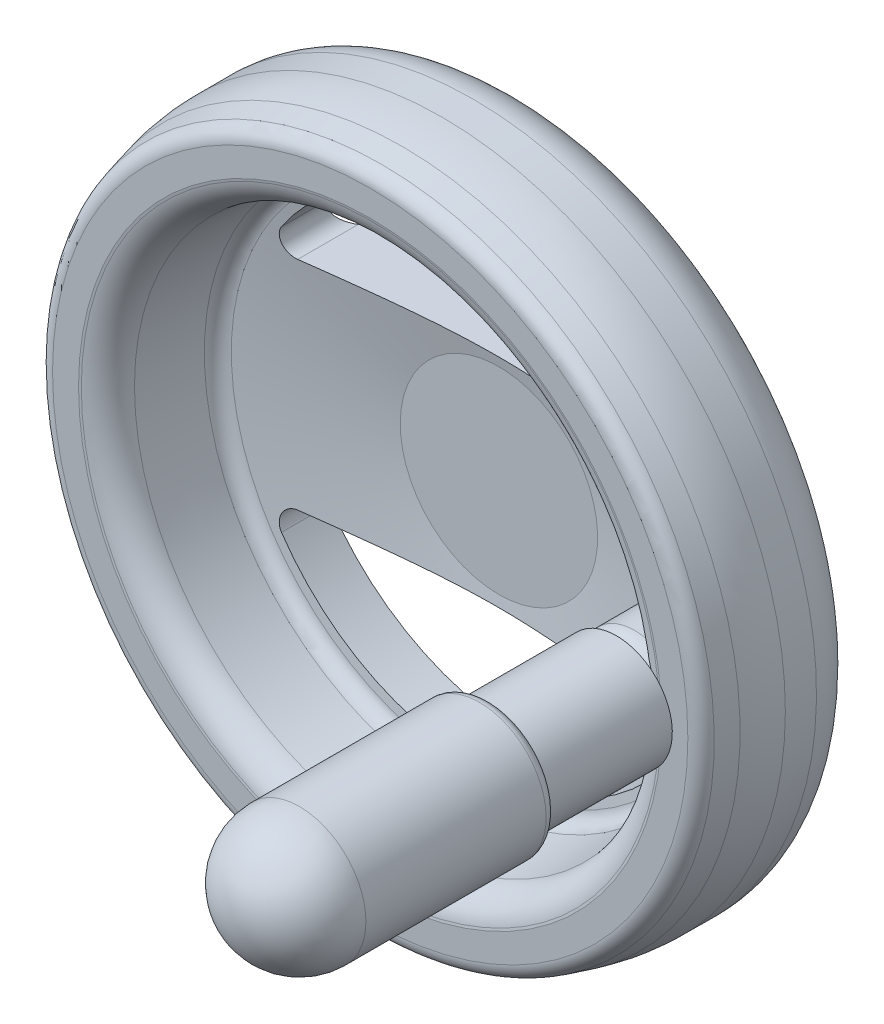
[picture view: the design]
ISO-10303-21;
HEADER;
FILE_DESCRIPTION(('STEP AP214'),'2;1');
FILE_NAME('part.step','',(''),(''),'','','');
FILE_SCHEMA(('AUTOMOTIVE_DESIGN { 1 0 10303 214 1 1 1 1 }'));
ENDSEC;
DATA;
#1=APPLICATION_CONTEXT('core data for automotive mechanical design processes');
#2=APPLICATION_PROTOCOL_DEFINITION('international standard','automotive_design',2000,#1);
#3=PRODUCT_CONTEXT('',#1,'mechanical');
#4=PRODUCT('Part','Part','',(#3));
#5=PRODUCT_RELATED_PRODUCT_CATEGORY('part','',(#4));
#6=PRODUCT_DEFINITION_FORMATION('','',#4);
#7=PRODUCT_DEFINITION_CONTEXT('part definition',#1,'design');
#8=PRODUCT_DEFINITION('design','',#6,#7);
#9=PRODUCT_DEFINITION_SHAPE('','',#8);
#10=(LENGTH_UNIT() NAMED_UNIT(*) SI_UNIT(.MILLI.,.METRE.));
#11=(NAMED_UNIT(*) PLANE_ANGLE_UNIT() SI_UNIT($,.RADIAN.));
#12=(NAMED_UNIT(*) SI_UNIT($,.STERADIAN.) SOLID_ANGLE_UNIT());
#13=UNCERTAINTY_MEASURE_WITH_UNIT(LENGTH_MEASURE(1.E-05),#10,'distance_accuracy_value','');
#14=(GEOMETRIC_REPRESENTATION_CONTEXT(3) GLOBAL_UNCERTAINTY_ASSIGNED_CONTEXT((#13)) GLOBAL_UNIT_ASSIGNED_CONTEXT((#10,
#11,#12)) REPRESENTATION_CONTEXT('',''));
#15=CARTESIAN_POINT('',(0.,0.,0.));
#16=DIRECTION('',(0.,0.,1.));
#17=DIRECTION('',(1.,0.,0.));
#18=AXIS2_PLACEMENT_3D('',#15,#16,#17);
#19=CARTESIAN_POINT('',(29.,0.,33.2));
#20=DIRECTION('',(0.,0.,-1.));
#21=DIRECTION('',(0.,1.,0.));
#22=AXIS2_PLACEMENT_3D('',#19,#20,#21);
#23=TOROIDAL_SURFACE('',#22,4.2,1.8);
#24=CARTESIAN_POINT('',(30.6761601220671,5.76111857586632,33.2));
#25=CARTESIAN_POINT('',(30.7059480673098,5.75244726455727,33.2481599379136));
#26=CARTESIAN_POINT('',(30.7369578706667,5.74116772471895,33.294989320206));
#27=CARTESIAN_POINT('',(30.8008570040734,5.71399772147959,33.3857792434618));
#28=CARTESIAN_POINT('',(30.8337414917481,5.69811874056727,33.429746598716));
#29=CARTESIAN_POINT('',(30.933707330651,5.64487432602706,33.5562676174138));
#30=CARTESIAN_POINT('',(31.0029129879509,5.60164089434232,33.6347145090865));
#31=CARTESIAN_POINT('',(31.1222333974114,5.51828977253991,33.7583522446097));
#32=CARTESIAN_POINT('',(31.1717108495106,5.48126584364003,33.8063746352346));
#33=CARTESIAN_POINT('',(31.2712263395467,5.40234334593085,33.8976094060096));
#34=CARTESIAN_POINT('',(31.3212644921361,5.36044376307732,33.9408207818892));
#35=CARTESIAN_POINT('',(31.4719915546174,5.22801287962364,34.0643305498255));
#36=CARTESIAN_POINT('',(31.5726915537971,5.13117834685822,34.1379051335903));
#37=CARTESIAN_POINT('',(31.7517457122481,4.94506324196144,34.2574365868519));
#38=CARTESIAN_POINT('',(31.8306722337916,4.85791259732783,34.3059835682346));
#39=CARTESIAN_POINT('',(31.9855051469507,4.67691643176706,34.3948959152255));
#40=CARTESIAN_POINT('',(32.0614097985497,4.58306713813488,34.4352566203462));
#41=CARTESIAN_POINT('',(32.2093597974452,4.38982890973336,34.5089751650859));
#42=CARTESIAN_POINT('',(32.2814060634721,4.29044130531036,34.5423346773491));
#43=CARTESIAN_POINT('',(32.4211196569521,4.08687545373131,34.6031213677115));
#44=CARTESIAN_POINT('',(32.4887858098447,3.9826959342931,34.6305469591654));
#45=CARTESIAN_POINT('',(32.6493058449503,3.72128500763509,34.6918239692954));
#46=CARTESIAN_POINT('',(32.7394256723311,3.56169671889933,34.7228268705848));
#47=CARTESIAN_POINT('',(32.9082571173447,3.23521266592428,34.7764231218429));
#48=CARTESIAN_POINT('',(32.9869639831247,3.06831389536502,34.7990129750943));
#49=CARTESIAN_POINT('',(33.1321341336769,2.72842101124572,34.8376545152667));
#50=CARTESIAN_POINT('',(33.1985893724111,2.5554229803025,34.853701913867));
#51=CARTESIAN_POINT('',(33.3184989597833,2.20463008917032,34.8807503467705));
#52=CARTESIAN_POINT('',(33.3719549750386,2.02683584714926,34.8917520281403));
#53=CARTESIAN_POINT('',(33.4662247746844,1.66421200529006,34.9100738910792));
#54=CARTESIAN_POINT('',(33.5067858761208,1.47931308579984,34.9173220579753));
#55=CARTESIAN_POINT('',(33.5735207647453,1.10684047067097,34.9287586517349));
#56=CARTESIAN_POINT('',(33.5996940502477,0.919266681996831,34.9329469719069));
#57=CARTESIAN_POINT('',(33.6374405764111,0.542670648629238,34.9388668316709));
#58=CARTESIAN_POINT('',(33.6490178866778,0.35364882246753,34.9405990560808));
#59=CARTESIAN_POINT('',(33.6575111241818,-0.0247321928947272,34.9418765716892));
#60=CARTESIAN_POINT('',(33.6544266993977,-0.214091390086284,34.9414218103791));
#61=CARTESIAN_POINT('',(33.6328597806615,-0.605655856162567,34.9381417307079));
#62=CARTESIAN_POINT('',(33.6132803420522,-0.807800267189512,34.9351474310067));
#63=CARTESIAN_POINT('',(33.5574365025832,-1.2097216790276,34.9260465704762));
#64=CARTESIAN_POINT('',(33.5211703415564,-1.40949842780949,34.9199396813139));
#65=CARTESIAN_POINT('',(33.4322821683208,-1.8053600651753,34.9036466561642));
#66=CARTESIAN_POINT('',(33.3796486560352,-2.00144225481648,34.893457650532));
#67=CARTESIAN_POINT('',(33.2586335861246,-2.3882898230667,34.8676070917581));
#68=CARTESIAN_POINT('',(33.190255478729,-2.57905635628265,34.8519467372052));
#69=CARTESIAN_POINT('',(33.0531328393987,-2.91785381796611,34.8170102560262));
#70=CARTESIAN_POINT('',(32.9869716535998,-3.06706637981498,34.7990028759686));
#71=CARTESIAN_POINT('',(32.8454480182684,-3.36022800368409,34.7569856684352));
#72=CARTESIAN_POINT('',(32.7700847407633,-3.50417659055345,34.7329753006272));
#73=CARTESIAN_POINT('',(32.6110214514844,-3.78548180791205,34.6775610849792));
#74=CARTESIAN_POINT('',(32.5273417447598,-3.9228533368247,34.6461750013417));
#75=CARTESIAN_POINT('',(32.3524095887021,-4.19007675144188,34.5742526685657));
#76=CARTESIAN_POINT('',(32.2611615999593,-4.31993299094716,34.5337217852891));
#77=CARTESIAN_POINT('',(32.0609092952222,-4.58555207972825,34.4358787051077));
#78=CARTESIAN_POINT('',(31.9510808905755,-4.72019973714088,34.377149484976));
#79=CARTESIAN_POINT('',(31.7819752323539,-4.91125842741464,34.2756717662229));
#80=CARTESIAN_POINT('',(31.7248471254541,-4.97315666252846,34.2395918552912));
#81=CARTESIAN_POINT('',(31.6095673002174,-5.09270339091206,34.1624008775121));
#82=CARTESIAN_POINT('',(31.5514158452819,-5.1503529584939,34.1212910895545));
#83=CARTESIAN_POINT('',(31.4063616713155,-5.28735403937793,34.0121924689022));
#84=CARTESIAN_POINT('',(31.3191359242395,-5.36374138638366,33.9408104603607));
#85=CARTESIAN_POINT('',(31.1464858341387,-5.50180113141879,33.7838796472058));
#86=CARTESIAN_POINT('',(31.0610543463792,-5.56355012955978,33.6984087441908));
#87=CARTESIAN_POINT('',(30.924797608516,-5.64924722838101,33.5444135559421));
#88=CARTESIAN_POINT('',(30.8723720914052,-5.67885122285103,33.4805071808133));
#89=CARTESIAN_POINT('',(30.7710499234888,-5.72811723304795,33.345539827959));
#90=CARTESIAN_POINT('',(30.7221859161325,-5.74769530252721,33.2744242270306));
#91=CARTESIAN_POINT('',(30.6761601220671,-5.76111857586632,33.2));
#92=B_SPLINE_CURVE_WITH_KNOTS('',3,(#24,#25,#26,#27,#28,#29,#30,#31,#32,#33,#34,#35,#36,#37,#38,
#39,#40,#41,#42,#43,#44,#45,#46,#47,#48,#49,#50,#51,#52,#53,#54,#55,#56,#57,#58,#59,#60,#61,#62,
#63,#64,#65,#66,#67,#68,#69,#70,#71,#72,#73,#74,#75,#76,#77,#78,#79,#80,#81,#82,#83,#84,#85,#86,
#87,#88,#89,#90,#91),.UNSPECIFIED.,.F.,.F.,(4,2,2,2,2,2,2,2,2,2,2,2,2,2,2,2,2,2,2,2,2,2,2,2,2,2,
2,2,2,2,2,2,2,4),(0.,0.17163547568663,0.342846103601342,0.68073967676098,0.915252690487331,
1.1498145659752,1.62175863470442,2.00292112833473,2.38430001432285,2.76558768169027,
3.1469771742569,3.70382900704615,4.2609120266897,4.81835960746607,5.37573568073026,
5.94344251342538,6.51116914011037,7.07873743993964,7.64631936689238,8.25492939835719,
8.86360364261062,9.47270652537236,10.0816760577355,10.573899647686,11.0661675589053,
11.557261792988,12.0480686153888,12.5968709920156,12.8715722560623,13.1462038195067,
13.5534597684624,13.9585350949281,14.2210901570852,14.4858090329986),.UNSPECIFIED.);
#93=CARTESIAN_POINT('',(30.6761601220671,5.76111857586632,33.2));
#94=VERTEX_POINT('',#93);
#95=CARTESIAN_POINT('',(30.6761601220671,-5.76111857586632,33.2));
#96=VERTEX_POINT('',#95);
#97=EDGE_CURVE('E163',#94,#96,#92,.T.);
#98=ORIENTED_EDGE('',*,*,#97,.F.);
#99=CARTESIAN_POINT('',(29.,0.,33.2));
#100=DIRECTION('',(0.,0.,1.));
#101=DIRECTION('',(0.,-1.,0.));
#102=AXIS2_PLACEMENT_3D('',#99,#100,#101);
#103=CIRCLE('',#102,6.);
#104=EDGE_CURVE('E159',#96,#94,#103,.F.);
#105=ORIENTED_EDGE('',*,*,#104,.F.);
#106=EDGE_LOOP('',(#98,#105));
#107=FACE_BOUND('',#106,.T.);
#108=CARTESIAN_POINT('',(29.,0.,35.));
#109=DIRECTION('',(0.,0.,-1.));
#110=DIRECTION('',(0.,-1.,0.));
#111=AXIS2_PLACEMENT_3D('',#108,#109,#110);
#112=CIRCLE('',#111,4.2);
#113=CARTESIAN_POINT('',(29.,-4.2,35.));
#114=VERTEX_POINT('',#113);
#115=CARTESIAN_POINT('',(24.8,0.,35.));
#116=VERTEX_POINT('',#115);
#117=EDGE_CURVE('E31',#114,#116,#112,.T.);
#118=ORIENTED_EDGE('',*,*,#117,.T.);
#119=CARTESIAN_POINT('',(29.,0.,35.));
#120=DIRECTION('',(0.,0.,-1.));
#121=DIRECTION('',(-1.,0.,0.));
#122=AXIS2_PLACEMENT_3D('',#119,#120,#121);
#123=CIRCLE('',#122,4.19999999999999);
#124=CARTESIAN_POINT('',(29.,4.2,35.));
#125=VERTEX_POINT('',#124);
#126=EDGE_CURVE('E788',#116,#125,#123,.T.);
#127=ORIENTED_EDGE('',*,*,#126,.T.);
#128=CARTESIAN_POINT('',(29.,0.,35.));
#129=DIRECTION('',(0.,0.,-1.));
#130=DIRECTION('',(0.,1.,0.));
#131=AXIS2_PLACEMENT_3D('',#128,#129,#130);
#132=CIRCLE('',#131,4.2);
#133=EDGE_CURVE('E786',#125,#114,#132,.T.);
#134=ORIENTED_EDGE('',*,*,#133,.T.);
#135=EDGE_LOOP('',(#118,#127,#134));
#136=FACE_BOUND('',#135,.T.);
#137=ADVANCED_FACE('F14',(#107,#136),#23,.T.);
#138=CARTESIAN_POINT('',(0.,0.,31.4060347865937));
#139=DIRECTION('',(0.,0.,-1.));
#140=DIRECTION('',(0.,1.,0.));
#141=AXIS2_PLACEMENT_3D('',#138,#139,#140);
#142=TOROIDAL_SURFACE('',#141,34.3336218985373,3.6);
#143=CARTESIAN_POINT('',(30.6761601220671,-5.76111857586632,33.2));
#144=CARTESIAN_POINT('',(30.6273849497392,-5.77530049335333,33.1211928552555));
#145=CARTESIAN_POINT('',(30.5816886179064,-5.78793211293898,33.0402070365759));
#146=CARTESIAN_POINT('',(30.4968646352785,-5.81045182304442,32.874468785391));
#147=CARTESIAN_POINT('',(30.4577389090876,-5.82033911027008,32.7897152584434));
#148=CARTESIAN_POINT('',(30.3871954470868,-5.83754874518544,32.6187736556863));
#149=CARTESIAN_POINT('',(30.3556414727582,-5.84491763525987,32.5326464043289));
#150=CARTESIAN_POINT('',(30.2995651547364,-5.8576409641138,32.3580312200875));
#151=CARTESIAN_POINT('',(30.2750393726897,-5.8629963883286,32.2695444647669));
#152=CARTESIAN_POINT('',(30.2364864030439,-5.87123762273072,32.1047832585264));
#153=CARTESIAN_POINT('',(30.2214171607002,-5.87437868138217,32.0287632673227));
#154=CARTESIAN_POINT('',(30.1963946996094,-5.87952217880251,31.8751872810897));
#155=CARTESIAN_POINT('',(30.1864857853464,-5.88151477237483,31.7976237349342));
#156=CARTESIAN_POINT('',(30.1792715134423,-5.88296852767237,31.7197954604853));
#157=B_SPLINE_CURVE_WITH_KNOTS('',3,(#143,#144,#145,#146,#147,#148,#149,#150,#151,#152,#153,
#154,#155,#156),.UNSPECIFIED.,.F.,.F.,(4,2,2,2,2,2,4),(0.,0.281182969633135,0.562448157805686,
0.838191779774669,1.11380027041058,1.3463037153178,1.58077173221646),.UNSPECIFIED.);
#158=CARTESIAN_POINT('',(30.1792715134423,-5.88296852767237,31.7197954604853));
#159=VERTEX_POINT('',#158);
#160=EDGE_CURVE('E170',#96,#159,#157,.T.);
#161=ORIENTED_EDGE('',*,*,#160,.T.);
#162=CARTESIAN_POINT('',(0.,0.,31.7197954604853));
#163=DIRECTION('',(0.,0.,1.));
#164=DIRECTION('',(-1.,0.,0.));
#165=AXIS2_PLACEMENT_3D('',#162,#163,#164);
#166=CIRCLE('',#165,30.747320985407);
#167=CARTESIAN_POINT('',(30.1792715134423,5.88296852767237,31.7197954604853));
#168=VERTEX_POINT('',#167);
#169=EDGE_CURVE('E167',#159,#168,#166,.F.);
#170=ORIENTED_EDGE('',*,*,#169,.T.);
#171=CARTESIAN_POINT('',(30.1792715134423,5.88296852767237,31.7197954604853));
#172=CARTESIAN_POINT('',(30.1879164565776,5.88121949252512,31.8131314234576));
#173=CARTESIAN_POINT('',(30.2004481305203,5.87870326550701,31.9060945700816));
#174=CARTESIAN_POINT('',(30.2331330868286,5.8719427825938,32.0906530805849));
#175=CARTESIAN_POINT('',(30.2532899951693,5.86769770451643,32.1822477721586));
#176=CARTESIAN_POINT('',(30.3005923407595,5.85739017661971,32.3615651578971));
#177=CARTESIAN_POINT('',(30.3275915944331,5.85136535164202,32.4493286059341));
#178=CARTESIAN_POINT('',(30.3885029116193,5.83721157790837,32.6221992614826));
#179=CARTESIAN_POINT('',(30.4224111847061,5.82908378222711,32.7073078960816));
#180=CARTESIAN_POINT('',(30.4910071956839,5.81187963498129,32.8612425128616));
#181=CARTESIAN_POINT('',(30.5247435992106,5.80315045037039,32.9305332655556));
#182=CARTESIAN_POINT('',(30.5969698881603,5.783691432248,33.0670662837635));
#183=CARTESIAN_POINT('',(30.6354977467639,5.77294522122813,33.1342861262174));
#184=CARTESIAN_POINT('',(30.6761601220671,5.76111857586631,33.2));
#185=B_SPLINE_CURVE_WITH_KNOTS('',3,(#171,#172,#173,#174,#175,#176,#177,#178,#179,#180,#181,
#182,#183,#184),.UNSPECIFIED.,.F.,.F.,(4,2,2,2,2,2,4),(0.,0.281175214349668,0.562484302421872,
0.838226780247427,1.11381838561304,1.34630753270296,1.58077317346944),.UNSPECIFIED.);
#186=EDGE_CURVE('E152',#168,#94,#185,.T.);
#187=ORIENTED_EDGE('',*,*,#186,.T.);
#188=ORIENTED_EDGE('',*,*,#97,.T.);
#189=EDGE_LOOP('',(#161,#170,#187,#188));
#190=FACE_BOUND('',#189,.T.);
#191=CARTESIAN_POINT('',(0.,0.,34.9513426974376));
#192=DIRECTION('',(0.,0.,1.));
#193=DIRECTION('',(-1.,0.,0.));
#194=AXIS2_PLACEMENT_3D('',#191,#192,#193);
#195=CIRCLE('',#194,33.7084884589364);
#196=CARTESIAN_POINT('',(-33.7084884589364,0.,34.9513426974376));
#197=VERTEX_POINT('',#196);
#198=EDGE_CURVE('E174',#197,#197,#195,.T.);
#199=ORIENTED_EDGE('',*,*,#198,.T.);
#200=EDGE_LOOP('',(#199));
#201=FACE_BOUND('',#200,.T.);
#202=ADVANCED_FACE('F168',(#190,#201),#142,.T.);
#203=CARTESIAN_POINT('',(29.,0.,26.6));
#204=DIRECTION('',(0.,0.,1.));
#205=DIRECTION('',(0.,-1.,0.));
#206=AXIS2_PLACEMENT_3D('',#203,#204,#205);
#207=CYLINDRICAL_SURFACE('',#206,6.);
#208=ORIENTED_EDGE('',*,*,#160,.F.);
#209=ORIENTED_EDGE('',*,*,#104,.T.);
#210=ORIENTED_EDGE('',*,*,#186,.F.);
#211=CARTESIAN_POINT('',(30.1792715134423,5.88296852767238,31.7197954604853));
#212=CARTESIAN_POINT('',(30.1214154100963,5.89456507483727,31.0960777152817));
#213=CARTESIAN_POINT('',(30.0637104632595,5.90524557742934,30.4723290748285));
#214=CARTESIAN_POINT('',(29.9486039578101,5.92482587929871,29.2247807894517));
#215=CARTESIAN_POINT('',(29.8912023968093,5.93372569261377,28.6009811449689));
#216=CARTESIAN_POINT('',(29.7767028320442,5.94979618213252,27.3533318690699));
#217=CARTESIAN_POINT('',(29.7196048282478,5.9569668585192,26.729482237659));
#218=CARTESIAN_POINT('',(29.605712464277,5.96962251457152,25.4817331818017));
#219=CARTESIAN_POINT('',(29.5489181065,5.97510748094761,24.8578337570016));
#220=CARTESIAN_POINT('',(29.4922760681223,5.97977125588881,24.2339144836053));
#221=B_SPLINE_CURVE_WITH_KNOTS('',3,(#211,#212,#213,#214,#215,#216,#217,#218,#219,#220),
.UNSPECIFIED.,.F.,.F.,(4,2,2,2,4),(0.,1.87950718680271,3.75899955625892,5.63849172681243,
7.51799871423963),.UNSPECIFIED.);
#222=CARTESIAN_POINT('',(29.4922760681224,5.9797712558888,24.2339144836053));
#223=VERTEX_POINT('',#222);
#224=EDGE_CURVE('E158',#168,#223,#221,.T.);
#225=ORIENTED_EDGE('',*,*,#224,.T.);
#226=CARTESIAN_POINT('',(29.4922760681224,5.9797712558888,24.2339144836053));
#227=CARTESIAN_POINT('',(29.4877633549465,5.98013823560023,24.1841300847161));
#228=CARTESIAN_POINT('',(29.4810885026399,5.98068702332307,24.1345484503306));
#229=CARTESIAN_POINT('',(29.4635155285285,5.98207700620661,24.0361553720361));
#230=CARTESIAN_POINT('',(29.4526184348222,5.9829181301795,23.9873437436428));
#231=CARTESIAN_POINT('',(29.4267261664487,5.98481988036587,23.890929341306));
#232=CARTESIAN_POINT('',(29.411739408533,5.98588005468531,23.8433243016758));
#233=CARTESIAN_POINT('',(29.37781218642,5.98811711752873,23.7495603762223));
#234=CARTESIAN_POINT('',(29.3588715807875,5.9892940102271,23.7034015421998));
#235=CARTESIAN_POINT('',(29.2963784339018,5.99282142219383,23.5676081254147));
#236=CARTESIAN_POINT('',(29.24711826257,5.99517190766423,23.4805228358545));
#237=CARTESIAN_POINT('',(29.1350562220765,5.99874082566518,23.3155665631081));
#238=CARTESIAN_POINT('',(29.0722493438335,5.99995883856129,23.2376990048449));
#239=CARTESIAN_POINT('',(28.9332068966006,6.0000400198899,23.0912280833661));
#240=CARTESIAN_POINT('',(28.8566741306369,5.99884338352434,23.0229059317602));
#241=CARTESIAN_POINT('',(28.6935876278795,5.9927259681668,22.8997674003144));
#242=CARTESIAN_POINT('',(28.6070362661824,5.98780607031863,22.8449478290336));
#243=CARTESIAN_POINT('',(28.4283761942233,5.97336344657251,22.7514437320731));
#244=CARTESIAN_POINT('',(28.3364353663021,5.9639462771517,22.7124253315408));
#245=CARTESIAN_POINT('',(28.195137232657,5.94596268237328,22.6656263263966));
#246=CARTESIAN_POINT('',(28.1474093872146,5.93931406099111,22.6519713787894));
#247=CARTESIAN_POINT('',(28.0511658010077,5.92470164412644,22.6286882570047));
#248=CARTESIAN_POINT('',(28.0026498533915,5.91673749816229,22.6190611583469));
#249=CARTESIAN_POINT('',(27.9539057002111,5.90810347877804,22.6114933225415));
#250=B_SPLINE_CURVE_WITH_KNOTS('',3,(#226,#227,#228,#229,#230,#231,#232,#233,#234,#235,#236,
#237,#238,#239,#240,#241,#242,#243,#244,#245,#246,#247,#248,#249),.UNSPECIFIED.,.F.,.F.,(4,2,2,
2,2,2,2,2,2,2,2,4),(0.,0.149914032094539,0.299791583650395,0.449362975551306,0.598939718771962,
0.897682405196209,1.19653574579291,1.50288175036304,1.80915527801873,2.10856926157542,
2.25866534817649,2.40880148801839),.UNSPECIFIED.);
#251=CARTESIAN_POINT('',(27.9539057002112,5.90810347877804,22.6114933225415));
#252=VERTEX_POINT('',#251);
#253=EDGE_CURVE('E180',#223,#252,#250,.T.);
#254=ORIENTED_EDGE('',*,*,#253,.T.);
#255=CARTESIAN_POINT('',(27.9539057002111,5.90810347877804,22.6114933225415));
#256=CARTESIAN_POINT('',(27.7862920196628,5.87844291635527,22.5854705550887));
#257=CARTESIAN_POINT('',(27.6199550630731,5.84161839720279,22.5594087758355));
#258=CARTESIAN_POINT('',(27.2909958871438,5.75397455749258,22.5074010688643));
#259=CARTESIAN_POINT('',(27.1283735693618,5.70315560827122,22.4814551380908));
#260=CARTESIAN_POINT('',(26.8080422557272,5.58787107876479,22.4298790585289));
#261=CARTESIAN_POINT('',(26.6503318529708,5.52340944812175,22.4042488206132));
#262=CARTESIAN_POINT('',(26.3408962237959,5.38127779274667,22.3535020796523));
#263=CARTESIAN_POINT('',(26.1891709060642,5.30360796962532,22.3283855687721));
#264=CARTESIAN_POINT('',(25.8927248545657,5.13555110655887,22.2788688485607));
#265=CARTESIAN_POINT('',(25.7480070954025,5.04515872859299,22.2544689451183));
#266=CARTESIAN_POINT('',(25.4666352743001,4.85226122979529,22.2066091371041));
#267=CARTESIAN_POINT('',(25.3299842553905,4.7497515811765,22.1831495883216));
#268=CARTESIAN_POINT('',(25.0659039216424,4.53343124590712,22.1374257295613));
#269=CARTESIAN_POINT('',(24.9384675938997,4.41962931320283,22.1151605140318));
#270=CARTESIAN_POINT('',(24.6935864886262,4.1813869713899,22.072027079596));
#271=CARTESIAN_POINT('',(24.5761462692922,4.05694176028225,22.0511594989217));
#272=CARTESIAN_POINT('',(24.3528772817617,3.79909969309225,22.0111845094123));
#273=CARTESIAN_POINT('',(24.2469830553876,3.66576104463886,21.9920672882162));
#274=CARTESIAN_POINT('',(24.0468497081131,3.39046440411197,21.955685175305));
#275=CARTESIAN_POINT('',(23.9526051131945,3.24851050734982,21.9384194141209));
#276=CARTESIAN_POINT('',(23.7763614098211,2.95679942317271,21.9059303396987));
#277=CARTESIAN_POINT('',(23.6943729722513,2.80703558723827,21.8907088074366));
#278=CARTESIAN_POINT('',(23.5434120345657,2.5009516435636,21.8625316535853));
#279=CARTESIAN_POINT('',(23.4744348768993,2.34463390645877,21.8495752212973));
#280=CARTESIAN_POINT('',(23.344419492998,2.01222464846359,21.825046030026));
#281=CARTESIAN_POINT('',(23.2846504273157,1.83561799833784,21.8137020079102));
#282=CARTESIAN_POINT('',(23.1817610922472,1.47743750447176,21.7941056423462));
#283=CARTESIAN_POINT('',(23.1386424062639,1.2958631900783,21.7858535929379));
#284=CARTESIAN_POINT('',(23.0694882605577,0.929404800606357,21.7725905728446));
#285=CARTESIAN_POINT('',(23.0434499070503,0.744521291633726,21.7675790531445));
#286=CARTESIAN_POINT('',(23.0087071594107,0.373087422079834,21.760887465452));
#287=CARTESIAN_POINT('',(23.0000007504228,0.186537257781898,21.7592070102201));
#288=CARTESIAN_POINT('',(22.9999993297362,-0.166611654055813,21.7592066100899));
#289=CARTESIAN_POINT('',(23.0069438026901,-0.333213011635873,21.7605468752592));
#290=CARTESIAN_POINT('',(23.0346693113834,-0.665277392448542,21.7658885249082));
#291=CARTESIAN_POINT('',(23.055454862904,-0.830740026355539,21.7698907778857));
#292=CARTESIAN_POINT('',(23.1106845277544,-1.15917029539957,21.780495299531));
#293=CARTESIAN_POINT('',(23.1451196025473,-1.32213950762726,21.7870958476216));
#294=CARTESIAN_POINT('',(23.2273930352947,-1.64459904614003,21.8028051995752));
#295=CARTESIAN_POINT('',(23.2752363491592,-1.80408806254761,21.811914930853));
#296=CARTESIAN_POINT('',(23.3839138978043,-2.11829984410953,21.8325079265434));
#297=CARTESIAN_POINT('',(23.4447395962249,-2.27302566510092,21.8439896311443));
#298=CARTESIAN_POINT('',(23.5789596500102,-2.57680131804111,21.8691808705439));
#299=CARTESIAN_POINT('',(23.6523583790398,-2.72584915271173,21.8828911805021));
#300=CARTESIAN_POINT('',(23.8111449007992,-3.01716720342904,21.9123587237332));
#301=CARTESIAN_POINT('',(23.8965305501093,-3.15943862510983,21.9281155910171));
#302=CARTESIAN_POINT('',(24.0786731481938,-3.43627658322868,21.961487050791));
#303=CARTESIAN_POINT('',(24.1754302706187,-3.57084300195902,21.97910167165));
#304=CARTESIAN_POINT('',(24.3805453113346,-3.83256196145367,22.0161544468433));
#305=CARTESIAN_POINT('',(24.4890007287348,-3.9596359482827,22.0356077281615));
#306=CARTESIAN_POINT('',(24.7159568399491,-4.204139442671,22.0759799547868));
#307=CARTESIAN_POINT('',(24.8344542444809,-4.32157208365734,22.0968984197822));
#308=CARTESIAN_POINT('',(25.0807887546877,-4.54616180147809,22.1400098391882));
#309=CARTESIAN_POINT('',(25.2086337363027,-4.65331003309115,22.1622038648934));
#310=CARTESIAN_POINT('',(25.472631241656,-4.85648058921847,22.2076278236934));
#311=CARTESIAN_POINT('',(25.6087808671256,-4.95250676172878,22.2308573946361));
#312=CARTESIAN_POINT('',(25.8908207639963,-5.1343574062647,22.278544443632));
#313=CARTESIAN_POINT('',(26.0368356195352,-5.2199850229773,22.3030159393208));
#314=CARTESIAN_POINT('',(26.3354346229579,-5.37853646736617,22.3525972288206));
#315=CARTESIAN_POINT('',(26.4880163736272,-5.45146488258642,22.3777067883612));
#316=CARTESIAN_POINT('',(26.7984817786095,-5.58406412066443,22.4283267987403));
#317=CARTESIAN_POINT('',(26.9563569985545,-5.64375497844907,22.4538365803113));
#318=CARTESIAN_POINT('',(27.2764707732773,-5.7495945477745,22.5050884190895));
#319=CARTESIAN_POINT('',(27.4387067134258,-5.79575118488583,22.5308303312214));
#320=CARTESIAN_POINT('',(27.6607579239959,-5.84893313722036,22.5657467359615));
#321=CARTESIAN_POINT('',(27.7191764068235,-5.86200273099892,22.5749035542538));
#322=CARTESIAN_POINT('',(27.8363111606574,-5.88637413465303,22.5932058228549));
#323=CARTESIAN_POINT('',(27.8950270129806,-5.89767795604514,22.6023512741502));
#324=CARTESIAN_POINT('',(27.9539057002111,-5.90810347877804,22.6114933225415));
#325=B_SPLINE_CURVE_WITH_KNOTS('',3,(#255,#256,#257,#258,#259,#260,#261,#262,#263,#264,#265,
#266,#267,#268,#269,#270,#271,#272,#273,#274,#275,#276,#277,#278,#279,#280,#281,#282,#283,#284,
#285,#286,#287,#288,#289,#290,#291,#292,#293,#294,#295,#296,#297,#298,#299,#300,#301,#302,#303,
#304,#305,#306,#307,#308,#309,#310,#311,#312,#313,#314,#315,#316,#317,#318,#319,#320,#321,#322,
#323,#324),.UNSPECIFIED.,.F.,.F.,(4,2,2,2,2,2,2,2,2,2,2,2,2,2,2,2,2,2,2,2,2,2,2,2,2,2,2,2,2,2,2,
2,2,2,4),(0.,0.516430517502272,1.03284733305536,1.54911484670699,2.06537448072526,
2.58185137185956,3.09852186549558,3.61479491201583,4.13130213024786,4.64470942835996,
5.15787455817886,5.67148390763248,6.18490905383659,6.74444002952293,7.30402420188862,
7.86351354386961,8.42293784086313,8.92260535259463,9.42243596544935,9.92193614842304,
10.4216211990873,10.9209786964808,11.4205102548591,11.9199526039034,12.4194025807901,
12.9233947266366,13.427222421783,13.9314796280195,14.4355618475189,14.9480511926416,
15.4603550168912,15.9718781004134,16.483101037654,16.6647579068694,16.8462063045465),.UNSPECIFIED.);
#326=CARTESIAN_POINT('',(27.9539057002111,-5.90810347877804,22.6114933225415));
#327=VERTEX_POINT('',#326);
#328=EDGE_CURVE('E247',#252,#327,#325,.T.);
#329=ORIENTED_EDGE('',*,*,#328,.T.);
#330=CARTESIAN_POINT('',(27.9539057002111,-5.90810347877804,22.6114933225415));
#331=CARTESIAN_POINT('',(28.0026384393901,-5.91673763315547,22.6190544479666));
#332=CARTESIAN_POINT('',(28.0511627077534,-5.92470212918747,22.6286854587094));
#333=CARTESIAN_POINT('',(28.1474236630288,-5.93931527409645,22.6519768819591));
#334=CARTESIAN_POINT('',(28.1951605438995,-5.94596425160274,22.6656362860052));
#335=CARTESIAN_POINT('',(28.2894075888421,-5.95796225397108,22.6968471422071));
#336=CARTESIAN_POINT('',(28.3359199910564,-5.96331382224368,22.7143908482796));
#337=CARTESIAN_POINT('',(28.4274650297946,-5.97279875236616,22.753232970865));
#338=CARTESIAN_POINT('',(28.4724976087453,-5.97693206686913,22.7745315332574));
#339=CARTESIAN_POINT('',(28.6048386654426,-5.9876246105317,22.8438051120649));
#340=CARTESIAN_POINT('',(28.6895245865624,-5.99249284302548,22.8972026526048));
#341=CARTESIAN_POINT('',(28.8493374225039,-5.99864354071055,23.016897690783));
#342=CARTESIAN_POINT('',(28.9244608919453,-5.99992471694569,23.0831998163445));
#343=CARTESIAN_POINT('',(29.0648059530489,-6.0000706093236,23.2288023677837));
#344=CARTESIAN_POINT('',(29.129735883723,-5.99887462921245,23.3083842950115));
#345=CARTESIAN_POINT('',(29.2453547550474,-5.99526173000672,23.4773175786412));
#346=CARTESIAN_POINT('',(29.2960474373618,-5.99284513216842,23.5666663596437));
#347=CARTESIAN_POINT('',(29.3594628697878,-5.98925814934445,23.7047976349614));
#348=CARTESIAN_POINT('',(29.3783165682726,-5.98808503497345,23.7508517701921));
#349=CARTESIAN_POINT('',(29.4120890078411,-5.98585579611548,23.8443955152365));
#350=CARTESIAN_POINT('',(29.4270079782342,-5.98479966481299,23.8918850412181));
#351=CARTESIAN_POINT('',(29.4527815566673,-5.98290564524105,23.9880466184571));
#352=CARTESIAN_POINT('',(29.4636289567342,-5.98206814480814,24.0367206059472));
#353=CARTESIAN_POINT('',(29.4811268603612,-5.98068389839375,24.1348338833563));
#354=CARTESIAN_POINT('',(29.4877762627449,-5.98013722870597,24.184273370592));
#355=CARTESIAN_POINT('',(29.4922760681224,-5.97977125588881,24.2339144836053));
#356=B_SPLINE_CURVE_WITH_KNOTS('',3,(#330,#331,#332,#333,#334,#335,#336,#337,#338,#339,#340,
#341,#342,#343,#344,#345,#346,#347,#348,#349,#350,#351,#352,#353,#354,#355),.UNSPECIFIED.,.F.,
.F.,(4,2,2,2,2,2,2,2,2,2,2,2,4),(0.,0.150141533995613,0.300245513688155,0.450052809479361,
0.599865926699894,0.899070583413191,1.19838274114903,1.50511543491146,1.8117674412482,
1.9609568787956,2.11013761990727,2.25958122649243,2.40906401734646),.UNSPECIFIED.);
#357=CARTESIAN_POINT('',(29.4922760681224,-5.97977125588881,24.2339144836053));
#358=VERTEX_POINT('',#357);
#359=EDGE_CURVE('E217',#327,#358,#356,.T.);
#360=ORIENTED_EDGE('',*,*,#359,.T.);
#361=CARTESIAN_POINT('',(29.4922760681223,-5.97977125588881,24.2339144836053));
#362=CARTESIAN_POINT('',(29.5489181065,-5.97510748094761,24.8578337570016));
#363=CARTESIAN_POINT('',(29.6057124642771,-5.96962251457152,25.4817331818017));
#364=CARTESIAN_POINT('',(29.7196048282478,-5.9569668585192,26.729482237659));
#365=CARTESIAN_POINT('',(29.7767028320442,-5.94979618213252,27.3533318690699));
#366=CARTESIAN_POINT('',(29.8912023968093,-5.93372569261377,28.6009811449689));
#367=CARTESIAN_POINT('',(29.9486039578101,-5.92482587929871,29.2247807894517));
#368=CARTESIAN_POINT('',(30.0637104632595,-5.90524557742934,30.4723290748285));
#369=CARTESIAN_POINT('',(30.1214154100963,-5.89456507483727,31.0960777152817));
#370=CARTESIAN_POINT('',(30.1792715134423,-5.88296852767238,31.7197954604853));
#371=B_SPLINE_CURVE_WITH_KNOTS('',3,(#361,#362,#363,#364,#365,#366,#367,#368,#369,#370),
.UNSPECIFIED.,.F.,.F.,(4,2,2,2,4),(0.,1.8795069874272,3.75899915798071,5.63849152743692,
7.51799871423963),.UNSPECIFIED.);
#372=EDGE_CURVE('E182',#358,#159,#371,.T.);
#373=ORIENTED_EDGE('',*,*,#372,.T.);
#374=EDGE_LOOP('',(#208,#209,#210,#225,#254,#329,#360,#373));
#375=FACE_BOUND('',#374,.T.);
#376=ADVANCED_FACE('F155',(#375),#207,.T.);
#377=CARTESIAN_POINT('',(0.,0.,31.7197954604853));
#378=DIRECTION('',(0.,0.,1.));
#379=DIRECTION('',(0.,-1.,0.));
#380=AXIS2_PLACEMENT_3D('',#377,#378,#379);
#381=CONICAL_SURFACE('',#380,30.747320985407,0.0872664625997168);
#382=CARTESIAN_POINT('',(0.,0.,24.2339144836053));
#383=DIRECTION('',(0.,0.,-1.));
#384=DIRECTION('',(0.,1.,0.));
#385=AXIS2_PLACEMENT_3D('',#382,#383,#384);
#386=CIRCLE('',#385,30.0923912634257);
#387=EDGE_CURVE('E178',#358,#223,#386,.T.);
#388=ORIENTED_EDGE('',*,*,#387,.T.);
#389=ORIENTED_EDGE('',*,*,#224,.F.);
#390=ORIENTED_EDGE('',*,*,#169,.F.);
#391=ORIENTED_EDGE('',*,*,#372,.F.);
#392=EDGE_LOOP('',(#388,#389,#390,#391));
#393=FACE_BOUND('',#392,.T.);
#394=ADVANCED_FACE('F177',(#393),#381,.F.);
#395=CARTESIAN_POINT('',(0.,0.,35.));
#396=DIRECTION('',(0.,0.,1.));
#397=DIRECTION('',(0.,-1.,0.));
#398=AXIS2_PLACEMENT_3D('',#395,#396,#397);
#399=CONICAL_SURFACE('',#398,33.9844377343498,1.39626340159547);
#400=CARTESIAN_POINT('',(0.,0.,35.));
#401=DIRECTION('',(0.,0.,1.));
#402=DIRECTION('',(0.,-1.,0.));
#403=AXIS2_PLACEMENT_3D('',#400,#401,#402);
#404=CIRCLE('',#403,33.9844377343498);
#405=CARTESIAN_POINT('',(0.,-33.9844377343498,35.));
#406=VERTEX_POINT('',#405);
#407=EDGE_CURVE('E224',#406,#406,#404,.F.);
#408=ORIENTED_EDGE('',*,*,#407,.F.);
#409=EDGE_LOOP('',(#408));
#410=FACE_BOUND('',#409,.T.);
#411=ORIENTED_EDGE('',*,*,#198,.F.);
#412=EDGE_LOOP('',(#411));
#413=FACE_BOUND('',#412,.T.);
#414=ADVANCED_FACE('F206',(#410,#413),#399,.F.);
#415=CARTESIAN_POINT('',(0.,0.,24.390794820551));
#416=DIRECTION('',(0.,0.,-1.));
#417=DIRECTION('',(0.,1.,0.));
#418=AXIS2_PLACEMENT_3D('',#415,#416,#417);
#419=TOROIDAL_SURFACE('',#418,28.2992408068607,1.79999999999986);
#420=CARTESIAN_POINT('',(0.,0.,22.6114933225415));
#421=DIRECTION('',(0.,0.,1.));
#422=DIRECTION('',(-1.,0.,0.));
#423=AXIS2_PLACEMENT_3D('',#420,#421,#422);
#424=CIRCLE('',#423,28.5714285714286);
#425=EDGE_CURVE('E244',#327,#252,#424,.F.);
#426=ORIENTED_EDGE('',*,*,#425,.T.);
#427=ORIENTED_EDGE('',*,*,#253,.F.);
#428=ORIENTED_EDGE('',*,*,#387,.F.);
#429=ORIENTED_EDGE('',*,*,#359,.F.);
#430=EDGE_LOOP('',(#426,#427,#428,#429));
#431=FACE_BOUND('',#430,.T.);
#432=ADVANCED_FACE('F226',(#431),#419,.F.);
#433=CARTESIAN_POINT('',(0.,0.,22.6114933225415));
#434=DIRECTION('',(0.,0.,1.));
#435=DIRECTION('',(0.,-1.,0.));
#436=AXIS2_PLACEMENT_3D('',#433,#434,#435);
#437=CONICAL_SURFACE('',#436,28.5714285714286,1.41899860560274);
#438=ORIENTED_EDGE('',*,*,#328,.F.);
#439=ORIENTED_EDGE('',*,*,#425,.F.);
#440=EDGE_LOOP('',(#438,#439));
#441=FACE_BOUND('',#440,.T.);
#442=CARTESIAN_POINT('',(21.3989308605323,-12.65,22.0434844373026));
#443=CARTESIAN_POINT('',(21.4495236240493,-12.650000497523,22.0501469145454));
#444=CARTESIAN_POINT('',(21.500068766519,-12.6521609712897,22.0569771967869));
#445=CARTESIAN_POINT('',(21.6007484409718,-12.6607693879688,22.0709245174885));
#446=CARTESIAN_POINT('',(21.6508830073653,-12.6672169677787,22.0780415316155));
#447=CARTESIAN_POINT('',(21.8000410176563,-12.6929129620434,22.0997264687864));
#448=CARTESIAN_POINT('',(21.8979933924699,-12.7185148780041,22.114651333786));
#449=CARTESIAN_POINT('',(22.0880610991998,-12.7858956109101,22.1449747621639));
#450=CARTESIAN_POINT('',(22.1801747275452,-12.8276791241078,22.1603734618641));
#451=CARTESIAN_POINT('',(22.3560012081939,-12.9262254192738,22.1912041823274));
#452=CARTESIAN_POINT('',(22.4397150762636,-12.9829863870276,22.2066361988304));
#453=CARTESIAN_POINT('',(22.5966134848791,-13.1100989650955,22.2371519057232));
#454=CARTESIAN_POINT('',(22.6697643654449,-13.1804924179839,22.2522343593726));
#455=CARTESIAN_POINT('',(22.803120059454,-13.3327931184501,22.2815927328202));
#456=CARTESIAN_POINT('',(22.8633232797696,-13.4147017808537,22.2958685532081));
#457=CARTESIAN_POINT('',(22.9688199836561,-13.5874485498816,22.3231871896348));
#458=CARTESIAN_POINT('',(23.0141590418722,-13.6782582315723,22.3362336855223));
#459=CARTESIAN_POINT('',(23.0887914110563,-13.8664335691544,22.3607987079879));
#460=CARTESIAN_POINT('',(23.1180868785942,-13.9637983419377,22.3723174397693));
#461=CARTESIAN_POINT('',(23.1595124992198,-14.1614135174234,22.393433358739));
#462=CARTESIAN_POINT('',(23.1717908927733,-14.2616311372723,22.4030465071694));
#463=CARTESIAN_POINT('',(23.1792116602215,-14.4629071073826,22.4202306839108));
#464=CARTESIAN_POINT('',(23.1743501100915,-14.5639656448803,22.4278012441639));
#465=CARTESIAN_POINT('',(23.1476859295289,-14.7629406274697,22.4406372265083));
#466=CARTESIAN_POINT('',(23.1260499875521,-14.8608781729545,22.4459245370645));
#467=CARTESIAN_POINT('',(23.0666008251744,-15.0517404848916,22.4541613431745));
#468=CARTESIAN_POINT('',(23.0288105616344,-15.1446721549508,22.4571141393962));
#469=CARTESIAN_POINT('',(22.9670461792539,-15.2661338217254,22.4595036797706));
#470=CARTESIAN_POINT('',(22.9495522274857,-15.2980622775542,22.4599823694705));
#471=CARTESIAN_POINT('',(22.9126691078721,-15.3607335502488,22.460619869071));
#472=CARTESIAN_POINT('',(22.8932832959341,-15.3914783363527,22.46077923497));
#473=CARTESIAN_POINT('',(22.8729664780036,-15.4216152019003,22.4607795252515));
#474=B_SPLINE_CURVE_WITH_KNOTS('',3,(#442,#443,#444,#445,#446,#447,#448,#449,#450,#451,#452,
#453,#454,#455,#456,#457,#458,#459,#460,#461,#462,#463,#464,#465,#466,#467,#468,#469,#470,#471,
#472,#473),.UNSPECIFIED.,.F.,.F.,(4,2,2,2,2,2,2,2,2,2,2,2,2,2,2,4),(0.,0.152992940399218,
0.305972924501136,0.61141124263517,0.91693827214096,1.22242831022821,1.52887129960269,
1.83535197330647,2.14088396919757,2.44637488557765,2.74918749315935,3.05206943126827,
3.35197958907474,3.65146495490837,3.76064188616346,3.86962855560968),.UNSPECIFIED.);
#475=CARTESIAN_POINT('',(21.3989308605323,-12.65,22.0434844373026));
#476=VERTEX_POINT('',#475);
#477=CARTESIAN_POINT('',(22.8729664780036,-15.4216152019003,22.4607795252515));
#478=VERTEX_POINT('',#477);
#479=EDGE_CURVE('E552',#476,#478,#474,.T.);
#480=ORIENTED_EDGE('',*,*,#479,.T.);
#481=CARTESIAN_POINT('',(0.,0.,22.4607795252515));
#482=DIRECTION('',(0.,0.,-1.));
#483=DIRECTION('',(0.,1.,0.));
#484=AXIS2_PLACEMENT_3D('',#481,#482,#483);
#485=CIRCLE('',#484,27.5862068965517);
#486=CARTESIAN_POINT('',(-22.8729664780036,-15.4216152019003,22.4607795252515));
#487=VERTEX_POINT('',#486);
#488=EDGE_CURVE('E660',#478,#487,#485,.T.);
#489=ORIENTED_EDGE('',*,*,#488,.T.);
#490=CARTESIAN_POINT('',(-22.8729664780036,-15.4216152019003,22.4607795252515));
#491=CARTESIAN_POINT('',(-22.9007186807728,-15.38045369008,22.4607794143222));
#492=CARTESIAN_POINT('',(-22.9267324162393,-15.338148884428,22.4604817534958));
#493=CARTESIAN_POINT('',(-22.9751293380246,-15.2515229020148,22.4592938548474));
#494=CARTESIAN_POINT('',(-22.9975127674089,-15.2072018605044,22.4584036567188));
#495=CARTESIAN_POINT('',(-23.0589155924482,-15.071780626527,22.4548524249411));
#496=CARTESIAN_POINT('',(-23.0922927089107,-14.9780659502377,22.451310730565));
#497=CARTESIAN_POINT('',(-23.1429603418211,-14.7865089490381,22.4419659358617));
#498=CARTESIAN_POINT('',(-23.1602448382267,-14.6886650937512,22.4361619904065));
#499=CARTESIAN_POINT('',(-23.1783130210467,-14.4916152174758,22.4224383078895));
#500=CARTESIAN_POINT('',(-23.1790986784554,-14.3924093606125,22.41451882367));
#501=CARTESIAN_POINT('',(-23.1641927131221,-14.1949970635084,22.3967231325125));
#502=CARTESIAN_POINT('',(-23.1484306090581,-14.0967967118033,22.3868387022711));
#503=CARTESIAN_POINT('',(-23.1008502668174,-13.9045450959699,22.3653806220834));
#504=CARTESIAN_POINT('',(-23.0690290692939,-13.8104946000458,22.3538066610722));
#505=CARTESIAN_POINT('',(-22.989916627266,-13.6282661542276,22.3291423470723));
#506=CARTESIAN_POINT('',(-22.9424799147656,-13.5401531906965,22.3160385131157));
#507=CARTESIAN_POINT('',(-22.8336281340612,-13.3732324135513,22.288742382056));
#508=CARTESIAN_POINT('',(-22.7722135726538,-13.2944242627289,22.2745501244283));
#509=CARTESIAN_POINT('',(-22.636490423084,-13.1475284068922,22.2453002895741));
#510=CARTESIAN_POINT('',(-22.5620606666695,-13.0795540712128,22.2302355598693));
#511=CARTESIAN_POINT('',(-22.4028227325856,-12.9571378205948,22.1997713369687));
#512=CARTESIAN_POINT('',(-22.318011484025,-12.9026999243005,22.1843717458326));
#513=CARTESIAN_POINT('',(-22.1398287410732,-12.8085835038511,22.1535682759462));
#514=CARTESIAN_POINT('',(-22.046403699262,-12.7690063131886,22.1381650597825));
#515=CARTESIAN_POINT('',(-21.8541638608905,-12.7063103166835,22.1079159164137));
#516=CARTESIAN_POINT('',(-21.7553557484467,-12.6831715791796,22.093069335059));
#517=CARTESIAN_POINT('',(-21.6128836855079,-12.6623975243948,22.0726527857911));
#518=CARTESIAN_POINT('',(-21.5702070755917,-12.6577484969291,22.0666609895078));
#519=CARTESIAN_POINT('',(-21.484675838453,-12.6515533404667,22.054901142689));
#520=CARTESIAN_POINT('',(-21.4418216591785,-12.6500017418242,22.049132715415));
#521=CARTESIAN_POINT('',(-21.3989308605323,-12.65,22.0434844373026));
#522=B_SPLINE_CURVE_WITH_KNOTS('',3,(#490,#491,#492,#493,#494,#495,#496,#497,#498,#499,#500,
#501,#502,#503,#504,#505,#506,#507,#508,#509,#510,#511,#512,#513,#514,#515,#516,#517,#518,#519,
#520,#521),.UNSPECIFIED.,.F.,.F.,(4,2,2,2,2,2,2,2,2,2,2,2,2,2,2,4),(0.,0.148837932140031,
0.297665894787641,0.594763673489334,0.891972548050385,1.1891459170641,1.48759018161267,
1.78608946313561,2.08745209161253,2.38880379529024,2.69312692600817,2.99754029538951,
3.30399327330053,3.61007403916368,3.74001820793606,3.8697327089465),.UNSPECIFIED.);
#523=CARTESIAN_POINT('',(-21.3989308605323,-12.65,22.0434844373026));
#524=VERTEX_POINT('',#523);
#525=EDGE_CURVE('E559',#487,#524,#522,.T.);
#526=ORIENTED_EDGE('',*,*,#525,.T.);
#527=CARTESIAN_POINT('',(21.3989308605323,-12.65,22.0434844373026));
#528=CARTESIAN_POINT('',(20.8795886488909,-12.65,21.9751037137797));
#529=CARTESIAN_POINT('',(20.3601645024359,-12.65,21.9073390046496));
#530=CARTESIAN_POINT('',(19.3211196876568,-12.65,21.7733099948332));
#531=CARTESIAN_POINT('',(18.801499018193,-12.65,21.7070457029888));
#532=CARTESIAN_POINT('',(17.7619947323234,-12.65,21.5762817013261));
#533=CARTESIAN_POINT('',(17.2421110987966,-12.65,21.5117821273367));
#534=CARTESIAN_POINT('',(16.2020857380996,-12.65,21.3848996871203));
#535=CARTESIAN_POINT('',(15.681944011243,-12.65,21.3225168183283));
#536=CARTESIAN_POINT('',(14.6398679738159,-12.65,21.2001144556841));
#537=CARTESIAN_POINT('',(14.1179328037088,-12.65,21.1401022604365));
#538=CARTESIAN_POINT('',(13.0737178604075,-12.65,21.0231554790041));
#539=CARTESIAN_POINT('',(12.5514380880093,-12.65,20.9662208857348));
#540=CARTESIAN_POINT('',(11.5064721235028,-12.65,20.856066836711));
#541=CARTESIAN_POINT('',(10.9837859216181,-12.65,20.8028474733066));
#542=CARTESIAN_POINT('',(9.93797370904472,-12.65,20.7008945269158));
#543=CARTESIAN_POINT('',(9.41484769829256,-12.65,20.6521609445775));
#544=CARTESIAN_POINT('',(8.372738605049,-12.65,20.5604899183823));
#545=CARTESIAN_POINT('',(7.85375971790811,-12.65,20.5175051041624));
#546=CARTESIAN_POINT('',(6.81531114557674,-12.65,20.4378248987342));
#547=CARTESIAN_POINT('',(6.29584145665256,-12.65,20.4011295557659));
#548=CARTESIAN_POINT('',(5.25646394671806,-12.65,20.3350894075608));
#549=CARTESIAN_POINT('',(4.73655615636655,-12.65,20.3057441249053));
#550=CARTESIAN_POINT('',(3.69634159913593,-12.65,20.2554281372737));
#551=CARTESIAN_POINT('',(3.17603484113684,-12.65,20.234457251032));
#552=CARTESIAN_POINT('',(2.13582587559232,-12.65,20.2017667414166));
#553=CARTESIAN_POINT('',(1.61592406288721,-12.65,20.190034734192));
#554=CARTESIAN_POINT('',(0.575990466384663,-12.65,20.1763044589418));
#555=CARTESIAN_POINT('',(0.0559586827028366,-12.65,20.1743061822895));
#556=CARTESIAN_POINT('',(-0.984058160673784,-12.65,20.1801384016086));
#557=CARTESIAN_POINT('',(-1.50404321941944,-12.65,20.187969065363));
#558=CARTESIAN_POINT('',(-2.54377893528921,-12.65,20.213094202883));
#559=CARTESIAN_POINT('',(-3.06352959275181,-12.65,20.2303886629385));
#560=CARTESIAN_POINT('',(-4.32610428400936,-12.65,20.283028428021));
#561=CARTESIAN_POINT('',(-5.06873846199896,-12.65,20.3229379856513));
#562=CARTESIAN_POINT('',(-6.55301604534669,-12.65,20.4177047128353));
#563=CARTESIAN_POINT('',(-7.29465946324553,-12.65,20.4725616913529));
#564=CARTESIAN_POINT('',(-8.7776655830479,-12.65,20.5942032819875));
#565=CARTESIAN_POINT('',(-9.51902734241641,-12.65,20.6609992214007));
#566=CARTESIAN_POINT('',(-11.0008660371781,-12.65,20.8037912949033));
#567=CARTESIAN_POINT('',(-11.7413429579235,-12.65,20.8797875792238));
#568=CARTESIAN_POINT('',(-13.2263962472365,-12.65,21.0393442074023));
#569=CARTESIAN_POINT('',(-13.9709675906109,-12.65,21.12295096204));
#570=CARTESIAN_POINT('',(-15.4594758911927,-12.65,21.2956250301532));
#571=CARTESIAN_POINT('',(-16.2034128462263,-12.65,21.3846923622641));
#572=CARTESIAN_POINT('',(-17.6895259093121,-12.65,21.5668680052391));
#573=CARTESIAN_POINT('',(-18.4317028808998,-12.65,21.6599693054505));
#574=CARTESIAN_POINT('',(-19.9156180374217,-12.65,21.8494713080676));
#575=CARTESIAN_POINT('',(-20.6573562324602,-12.65,21.9458719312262));
#576=CARTESIAN_POINT('',(-21.3989308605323,-12.65,22.0434844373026));
#577=B_SPLINE_CURVE_WITH_KNOTS('',3,(#527,#528,#529,#530,#531,#532,#533,#534,#535,#536,#537,
#538,#539,#540,#541,#542,#543,#544,#545,#546,#547,#548,#549,#550,#551,#552,#553,#554,#555,#556,
#557,#558,#559,#560,#561,#562,#563,#564,#565,#566,#567,#568,#569,#570,#571,#572,#573,#574,#575,
#576),.UNSPECIFIED.,.F.,.F.,(4,2,2,2,2,2,2,2,2,2,2,2,2,2,2,2,2,2,2,2,2,2,2,2,4),(0.,
1.57147478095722,3.14295882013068,4.71456347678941,6.28616622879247,7.86228056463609,
9.43839127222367,11.0145411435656,12.5906912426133,14.1529270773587,15.71517489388,
17.2773212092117,18.8394337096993,20.399448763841,21.9594624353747,23.5195027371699,
25.0795407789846,27.3104614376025,29.5413535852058,31.7743736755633,34.0074302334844,
36.2551563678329,38.5028901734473,40.7468631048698,42.9907821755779),.UNSPECIFIED.);
#578=EDGE_CURVE('E246',#476,#524,#577,.T.);
#579=ORIENTED_EDGE('',*,*,#578,.F.);
#580=EDGE_LOOP('',(#480,#489,#526,#579));
#581=FACE_BOUND('',#580,.T.);
#582=CARTESIAN_POINT('',(0.,0.,20.));
#583=DIRECTION('',(0.,0.,1.));
#584=DIRECTION('',(0.,-1.,0.));
#585=AXIS2_PLACEMENT_3D('',#582,#583,#584);
#586=CIRCLE('',#585,11.5);
#587=CARTESIAN_POINT('',(0.,-11.5,20.));
#588=VERTEX_POINT('',#587);
#589=EDGE_CURVE('E1322',#588,#588,#586,.T.);
#590=ORIENTED_EDGE('',*,*,#589,.F.);
#591=EDGE_LOOP('',(#590));
#592=FACE_BOUND('',#591,.T.);
#593=CARTESIAN_POINT('',(22.8729664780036,15.4216152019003,22.4607795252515));
#594=CARTESIAN_POINT('',(22.9007186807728,15.38045369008,22.4607794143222));
#595=CARTESIAN_POINT('',(22.9267324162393,15.338148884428,22.4604817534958));
#596=CARTESIAN_POINT('',(22.9751293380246,15.2515229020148,22.4592938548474));
#597=CARTESIAN_POINT('',(22.9975127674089,15.2072018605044,22.4584036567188));
#598=CARTESIAN_POINT('',(23.0589155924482,15.071780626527,22.4548524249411));
#599=CARTESIAN_POINT('',(23.0922927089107,14.9780659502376,22.451310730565));
#600=CARTESIAN_POINT('',(23.1429603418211,14.786508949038,22.4419659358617));
#601=CARTESIAN_POINT('',(23.1602448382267,14.6886650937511,22.4361619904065));
#602=CARTESIAN_POINT('',(23.1783130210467,14.4916152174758,22.4224383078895));
#603=CARTESIAN_POINT('',(23.1790986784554,14.3924093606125,22.41451882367));
#604=CARTESIAN_POINT('',(23.1641927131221,14.1949970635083,22.3967231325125));
#605=CARTESIAN_POINT('',(23.1484306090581,14.0967967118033,22.3868387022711));
#606=CARTESIAN_POINT('',(23.1008502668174,13.9045450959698,22.3653806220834));
#607=CARTESIAN_POINT('',(23.0690290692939,13.8104946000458,22.3538066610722));
#608=CARTESIAN_POINT('',(22.989916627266,13.6282661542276,22.3291423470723));
#609=CARTESIAN_POINT('',(22.9424799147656,13.5401531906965,22.3160385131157));
#610=CARTESIAN_POINT('',(22.8336281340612,13.3732324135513,22.288742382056));
#611=CARTESIAN_POINT('',(22.7722135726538,13.2944242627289,22.2745501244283));
#612=CARTESIAN_POINT('',(22.636490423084,13.1475284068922,22.2453002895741));
#613=CARTESIAN_POINT('',(22.5620606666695,13.0795540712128,22.2302355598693));
#614=CARTESIAN_POINT('',(22.4028227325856,12.9571378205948,22.1997713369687));
#615=CARTESIAN_POINT('',(22.318011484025,12.9026999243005,22.1843717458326));
#616=CARTESIAN_POINT('',(22.1398287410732,12.8085835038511,22.1535682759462));
#617=CARTESIAN_POINT('',(22.046403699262,12.7690063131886,22.1381650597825));
#618=CARTESIAN_POINT('',(21.8541638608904,12.7063103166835,22.1079159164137));
#619=CARTESIAN_POINT('',(21.7553557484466,12.6831715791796,22.093069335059));
#620=CARTESIAN_POINT('',(21.6128836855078,12.6623975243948,22.0726527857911));
#621=CARTESIAN_POINT('',(21.5702070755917,12.6577484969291,22.0666609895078));
#622=CARTESIAN_POINT('',(21.484675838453,12.6515533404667,22.054901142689));
#623=CARTESIAN_POINT('',(21.4418216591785,12.6500017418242,22.049132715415));
#624=CARTESIAN_POINT('',(21.3989308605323,12.65,22.0434844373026));
#625=B_SPLINE_CURVE_WITH_KNOTS('',3,(#593,#594,#595,#596,#597,#598,#599,#600,#601,#602,#603,
#604,#605,#606,#607,#608,#609,#610,#611,#612,#613,#614,#615,#616,#617,#618,#619,#620,#621,#622,
#623,#624),.UNSPECIFIED.,.F.,.F.,(4,2,2,2,2,2,2,2,2,2,2,2,2,2,2,4),(0.,0.148837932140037,
0.29766589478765,0.594763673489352,0.891972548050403,1.18914591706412,1.48759018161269,
1.78608946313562,2.08745209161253,2.38880379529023,2.69312692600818,2.99754029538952,
3.30399327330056,3.61007403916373,3.74001820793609,3.8697327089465),.UNSPECIFIED.);
#626=CARTESIAN_POINT('',(22.8729664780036,15.4216152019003,22.4607795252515));
#627=VERTEX_POINT('',#626);
#628=CARTESIAN_POINT('',(21.3989308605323,12.65,22.0434844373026));
#629=VERTEX_POINT('',#628);
#630=EDGE_CURVE('E502',#627,#629,#625,.T.);
#631=ORIENTED_EDGE('',*,*,#630,.T.);
#632=CARTESIAN_POINT('',(21.3989308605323,12.65,22.0434844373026));
#633=CARTESIAN_POINT('',(20.8795886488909,12.65,21.9751037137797));
#634=CARTESIAN_POINT('',(20.3601645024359,12.65,21.9073390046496));
#635=CARTESIAN_POINT('',(19.3211196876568,12.65,21.7733099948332));
#636=CARTESIAN_POINT('',(18.801499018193,12.65,21.7070457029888));
#637=CARTESIAN_POINT('',(17.7619947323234,12.65,21.5762817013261));
#638=CARTESIAN_POINT('',(17.2421110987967,12.65,21.5117821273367));
#639=CARTESIAN_POINT('',(16.2020857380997,12.65,21.3848996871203));
#640=CARTESIAN_POINT('',(15.681944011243,12.65,21.3225168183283));
#641=CARTESIAN_POINT('',(14.639867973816,12.65,21.2001144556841));
#642=CARTESIAN_POINT('',(14.1179328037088,12.65,21.1401022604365));
#643=CARTESIAN_POINT('',(13.0737178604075,12.65,21.0231554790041));
#644=CARTESIAN_POINT('',(12.5514380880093,12.65,20.9662208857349));
#645=CARTESIAN_POINT('',(11.5064721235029,12.65,20.856066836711));
#646=CARTESIAN_POINT('',(10.9837859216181,12.65,20.8028474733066));
#647=CARTESIAN_POINT('',(9.93797370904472,12.65,20.7008945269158));
#648=CARTESIAN_POINT('',(9.41484769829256,12.65,20.6521609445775));
#649=CARTESIAN_POINT('',(8.37273860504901,12.65,20.5604899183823));
#650=CARTESIAN_POINT('',(7.85375971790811,12.65,20.5175051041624));
#651=CARTESIAN_POINT('',(6.81531114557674,12.65,20.4378248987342));
#652=CARTESIAN_POINT('',(6.29584145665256,12.65,20.4011295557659));
#653=CARTESIAN_POINT('',(5.25646394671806,12.65,20.3350894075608));
#654=CARTESIAN_POINT('',(4.73655615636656,12.65,20.3057441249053));
#655=CARTESIAN_POINT('',(3.69634159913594,12.65,20.2554281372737));
#656=CARTESIAN_POINT('',(3.17603484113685,12.65,20.234457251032));
#657=CARTESIAN_POINT('',(2.13582587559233,12.65,20.2017667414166));
#658=CARTESIAN_POINT('',(1.61592406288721,12.65,20.190034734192));
#659=CARTESIAN_POINT('',(0.575990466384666,12.65,20.1763044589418));
#660=CARTESIAN_POINT('',(0.0559586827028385,12.65,20.1743061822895));
#661=CARTESIAN_POINT('',(-0.984058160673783,12.65,20.1801384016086));
#662=CARTESIAN_POINT('',(-1.50404321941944,12.65,20.187969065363));
#663=CARTESIAN_POINT('',(-2.54377893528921,12.65,20.213094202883));
#664=CARTESIAN_POINT('',(-3.0635295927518,12.65,20.2303886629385));
#665=CARTESIAN_POINT('',(-4.32610428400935,12.65,20.283028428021));
#666=CARTESIAN_POINT('',(-5.06873846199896,12.65,20.3229379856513));
#667=CARTESIAN_POINT('',(-6.55301604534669,12.65,20.4177047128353));
#668=CARTESIAN_POINT('',(-7.29465946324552,12.65,20.4725616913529));
#669=CARTESIAN_POINT('',(-8.77766558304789,12.65,20.5942032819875));
#670=CARTESIAN_POINT('',(-9.51902734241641,12.65,20.6609992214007));
#671=CARTESIAN_POINT('',(-11.0008660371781,12.65,20.8037912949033));
#672=CARTESIAN_POINT('',(-11.7413429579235,12.65,20.8797875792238));
#673=CARTESIAN_POINT('',(-13.2263962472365,12.65,21.0393442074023));
#674=CARTESIAN_POINT('',(-13.9709675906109,12.65,21.12295096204));
#675=CARTESIAN_POINT('',(-15.4594758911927,12.65,21.2956250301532));
#676=CARTESIAN_POINT('',(-16.2034128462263,12.65,21.3846923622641));
#677=CARTESIAN_POINT('',(-17.6895259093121,12.65,21.5668680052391));
#678=CARTESIAN_POINT('',(-18.4317028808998,12.65,21.6599693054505));
#679=CARTESIAN_POINT('',(-19.9156180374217,12.65,21.8494713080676));
#680=CARTESIAN_POINT('',(-20.6573562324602,12.65,21.9458719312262));
#681=CARTESIAN_POINT('',(-21.3989308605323,12.65,22.0434844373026));
#682=B_SPLINE_CURVE_WITH_KNOTS('',3,(#632,#633,#634,#635,#636,#637,#638,#639,#640,#641,#642,
#643,#644,#645,#646,#647,#648,#649,#650,#651,#652,#653,#654,#655,#656,#657,#658,#659,#660,#661,
#662,#663,#664,#665,#666,#667,#668,#669,#670,#671,#672,#673,#674,#675,#676,#677,#678,#679,#680,
#681),.UNSPECIFIED.,.F.,.F.,(4,2,2,2,2,2,2,2,2,2,2,2,2,2,2,2,2,2,2,2,2,2,2,2,4),(0.,
1.57147478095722,3.14295882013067,4.7145634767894,6.28616622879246,7.86228056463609,
9.43839127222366,11.0145411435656,12.5906912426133,14.1529270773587,15.71517489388,
17.2773212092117,18.8394337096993,20.399448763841,21.9594624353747,23.5195027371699,
25.0795407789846,27.3104614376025,29.5413535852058,31.7743736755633,34.0074302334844,
36.2551563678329,38.5028901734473,40.7468631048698,42.9907821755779),.UNSPECIFIED.);
#683=CARTESIAN_POINT('',(-21.3989308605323,12.65,22.0434844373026));
#684=VERTEX_POINT('',#683);
#685=EDGE_CURVE('E253',#629,#684,#682,.T.);
#686=ORIENTED_EDGE('',*,*,#685,.T.);
#687=CARTESIAN_POINT('',(-21.3989308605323,12.65,22.0434844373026));
#688=CARTESIAN_POINT('',(-21.4495236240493,12.650000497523,22.0501469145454));
#689=CARTESIAN_POINT('',(-21.5000687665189,12.6521609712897,22.0569771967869));
#690=CARTESIAN_POINT('',(-21.6007484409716,12.6607693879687,22.0709245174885));
#691=CARTESIAN_POINT('',(-21.6508830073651,12.6672169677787,22.0780415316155));
#692=CARTESIAN_POINT('',(-21.8000410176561,12.6929129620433,22.0997264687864));
#693=CARTESIAN_POINT('',(-21.8979933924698,12.718514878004,22.1146513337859));
#694=CARTESIAN_POINT('',(-22.0880610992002,12.7858956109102,22.144974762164));
#695=CARTESIAN_POINT('',(-22.1801747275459,12.8276791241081,22.1603734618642));
#696=CARTESIAN_POINT('',(-22.3560012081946,12.9262254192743,22.1912041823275));
#697=CARTESIAN_POINT('',(-22.4397150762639,12.9829863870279,22.2066361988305));
#698=CARTESIAN_POINT('',(-22.5966134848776,13.1100989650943,22.2371519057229));
#699=CARTESIAN_POINT('',(-22.669764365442,13.1804924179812,22.2522343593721));
#700=CARTESIAN_POINT('',(-22.8031200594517,13.332793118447,22.2815927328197));
#701=CARTESIAN_POINT('',(-22.8633232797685,13.4147017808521,22.2958685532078));
#702=CARTESIAN_POINT('',(-22.9688199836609,13.5874485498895,22.323187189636));
#703=CARTESIAN_POINT('',(-23.0141590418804,13.6782582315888,22.3362336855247));
#704=CARTESIAN_POINT('',(-23.0887914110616,13.8664335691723,22.36079870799));
#705=CARTESIAN_POINT('',(-23.1180868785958,13.9637983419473,22.3723174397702));
#706=CARTESIAN_POINT('',(-23.1595124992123,14.1614135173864,22.3934333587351));
#707=CARTESIAN_POINT('',(-23.1717908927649,14.261631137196,22.4030465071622));
#708=CARTESIAN_POINT('',(-23.1792116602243,14.4629071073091,22.4202306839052));
#709=CARTESIAN_POINT('',(-23.1743501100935,14.5639656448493,22.4278012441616));
#710=CARTESIAN_POINT('',(-23.1476859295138,14.7629406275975,22.4406372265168));
#711=CARTESIAN_POINT('',(-23.1260499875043,14.8608781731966,22.4459245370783));
#712=CARTESIAN_POINT('',(-23.0666008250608,15.0517404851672,22.4541613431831));
#713=CARTESIAN_POINT('',(-23.0288105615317,15.1446721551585,22.4571141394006));
#714=CARTESIAN_POINT('',(-22.9670462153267,15.2661337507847,22.4595036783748));
#715=CARTESIAN_POINT('',(-22.9495523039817,15.2980621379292,22.4599823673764));
#716=CARTESIAN_POINT('',(-22.912669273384,15.3607332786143,22.4606198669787));
#717=CARTESIAN_POINT('',(-22.8932835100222,15.3914780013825,22.4607792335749));
#718=CARTESIAN_POINT('',(-22.8729667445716,15.4216148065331,22.4607795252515));
#719=B_SPLINE_CURVE_WITH_KNOTS('',3,(#687,#688,#689,#690,#691,#692,#693,#694,#695,#696,#697,
#698,#699,#700,#701,#702,#703,#704,#705,#706,#707,#708,#709,#710,#711,#712,#713,#714,#715,#716,
#717,#718),.UNSPECIFIED.,.F.,.F.,(4,2,2,2,2,2,2,2,2,2,2,2,2,2,2,4),(0.,0.152992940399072,
0.305972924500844,0.611411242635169,0.916938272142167,1.22242831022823,1.52887129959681,
1.83535197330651,2.14088396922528,2.44637488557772,2.74918749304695,3.05206943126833,
3.35197958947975,3.65146495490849,3.7606416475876,3.86962807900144),.UNSPECIFIED.);
#720=CARTESIAN_POINT('',(-22.8729667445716,15.4216148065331,22.4607795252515));
#721=VERTEX_POINT('',#720);
#722=EDGE_CURVE('E517',#684,#721,#719,.T.);
#723=ORIENTED_EDGE('',*,*,#722,.T.);
#724=CARTESIAN_POINT('',(0.,0.,22.4607795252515));
#725=DIRECTION('',(0.,0.,-1.));
#726=DIRECTION('',(0.,1.,0.));
#727=AXIS2_PLACEMENT_3D('',#724,#725,#726);
#728=CIRCLE('',#727,27.5862068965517);
#729=EDGE_CURVE('E667',#721,#627,#728,.T.);
#730=ORIENTED_EDGE('',*,*,#729,.T.);
#731=EDGE_LOOP('',(#631,#686,#723,#730));
#732=FACE_BOUND('',#731,.T.);
#733=ADVANCED_FACE('F231',(#441,#581,#592,#732),#437,.F.);
#734=CARTESIAN_POINT('',(-35.4977770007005,0.,35.));
#735=DIRECTION('',(0.,0.,1.));
#736=DIRECTION('',(0.,-1.,0.));
#737=AXIS2_PLACEMENT_3D('',#734,#735,#736);
#738=PLANE('',#737);
#739=ORIENTED_EDGE('',*,*,#407,.T.);
#740=EDGE_LOOP('',(#739));
#741=FACE_BOUND('',#740,.T.);
#742=CARTESIAN_POINT('',(0.,0.,35.));
#743=DIRECTION('',(0.,0.,-1.));
#744=DIRECTION('',(0.,-1.,0.));
#745=AXIS2_PLACEMENT_3D('',#742,#743,#744);
#746=CIRCLE('',#745,37.0111162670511);
#747=CARTESIAN_POINT('',(0.,-37.0111162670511,35.));
#748=VERTEX_POINT('',#747);
#749=CARTESIAN_POINT('',(-37.0111162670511,0.,35.));
#750=VERTEX_POINT('',#749);
#751=EDGE_CURVE('E1358',#748,#750,#746,.T.);
#752=ORIENTED_EDGE('',*,*,#751,.F.);
#753=CARTESIAN_POINT('',(0.,0.,35.));
#754=DIRECTION('',(0.,0.,-1.));
#755=DIRECTION('',(0.,1.,0.));
#756=AXIS2_PLACEMENT_3D('',#753,#754,#755);
#757=CIRCLE('',#756,37.0111162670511);
#758=CARTESIAN_POINT('',(0.,37.0111162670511,35.));
#759=VERTEX_POINT('',#758);
#760=EDGE_CURVE('E1368',#759,#748,#757,.T.);
#761=ORIENTED_EDGE('',*,*,#760,.F.);
#762=CARTESIAN_POINT('',(0.,0.,35.));
#763=DIRECTION('',(0.,0.,-1.));
#764=DIRECTION('',(-1.,0.,0.));
#765=AXIS2_PLACEMENT_3D('',#762,#763,#764);
#766=CIRCLE('',#765,37.0111162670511);
#767=EDGE_CURVE('E1347',#750,#759,#766,.T.);
#768=ORIENTED_EDGE('',*,*,#767,.F.);
#769=EDGE_LOOP('',(#752,#761,#768));
#770=FACE_BOUND('',#769,.T.);
#771=ADVANCED_FACE('F233',(#741,#770),#738,.T.);
#772=CARTESIAN_POINT('',(21.3989308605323,-14.4277777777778,0.));
#773=DIRECTION('',(0.,0.,-1.));
#774=DIRECTION('',(0.,1.,0.));
#775=AXIS2_PLACEMENT_3D('',#772,#773,#774);
#776=CYLINDRICAL_SURFACE('',#775,1.77777777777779);
#777=DIRECTION('',(0.,0.,-1.));
#778=VECTOR('',#777,1.);
#779=CARTESIAN_POINT('',(22.8729664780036,-15.4216152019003,0.));
#780=LINE('',#779,#778);
#781=CARTESIAN_POINT('',(22.8729664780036,-15.4216152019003,16.8416052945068));
#782=VERTEX_POINT('',#781);
#783=EDGE_CURVE('E657',#782,#478,#780,.F.);
#784=ORIENTED_EDGE('',*,*,#783,.T.);
#785=ORIENTED_EDGE('',*,*,#479,.F.);
#786=DIRECTION('',(0.,0.,-1.));
#787=VECTOR('',#786,1.);
#788=CARTESIAN_POINT('',(21.3989308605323,-12.65,0.));
#789=LINE('',#788,#787);
#790=CARTESIAN_POINT('',(21.3989308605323,-12.65,14.9782932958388));
#791=VERTEX_POINT('',#790);
#792=EDGE_CURVE('E661',#791,#476,#789,.F.);
#793=ORIENTED_EDGE('',*,*,#792,.F.);
#794=CARTESIAN_POINT('',(22.7836981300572,-13.3129175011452,16.2068560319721));
#795=CARTESIAN_POINT('',(22.745977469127,-13.2660802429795,16.1617237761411));
#796=CARTESIAN_POINT('',(22.7061736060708,-13.2214903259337,16.1160758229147));
#797=CARTESIAN_POINT('',(22.6227539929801,-13.1369307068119,16.0240217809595));
#798=CARTESIAN_POINT('',(22.5791393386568,-13.096959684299,15.9776159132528));
#799=CARTESIAN_POINT('',(22.4426527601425,-12.9837735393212,15.8371959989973));
#800=CARTESIAN_POINT('',(22.344496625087,-12.9177249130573,15.7424058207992));
#801=CARTESIAN_POINT('',(22.1302005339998,-12.802506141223,15.5470962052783));
#802=CARTESIAN_POINT('',(22.0133082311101,-12.7547030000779,15.4466024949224));
#803=CARTESIAN_POINT('',(21.7698021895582,-12.6845298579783,15.2491942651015));
#804=CARTESIAN_POINT('',(21.6432295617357,-12.6620580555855,15.1522669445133));
#805=CARTESIAN_POINT('',(21.4754888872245,-12.6512453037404,15.0317500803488));
#806=CARTESIAN_POINT('',(21.4373276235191,-12.6500033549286,15.0048419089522));
#807=CARTESIAN_POINT('',(21.3989308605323,-12.65,14.9782932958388));
#808=B_SPLINE_CURVE_WITH_KNOTS('',3,(#794,#795,#796,#797,#798,#799,#800,#801,#802,#803,#804,
#805,#806,#807),.UNSPECIFIED.,.F.,.F.,(4,2,2,2,2,2,4),(0.,0.225422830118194,0.450781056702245,
0.903602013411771,1.38569343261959,1.86584044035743,2.00590562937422),.UNSPECIFIED.);
#809=CARTESIAN_POINT('',(22.7836981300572,-13.3129175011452,16.2068560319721));
#810=VERTEX_POINT('',#809);
#811=EDGE_CURVE('E592',#810,#791,#808,.T.);
#812=ORIENTED_EDGE('',*,*,#811,.F.);
#813=CARTESIAN_POINT('',(22.7836981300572,-13.3129175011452,16.2068560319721));
#814=CARTESIAN_POINT('',(22.8090614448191,-13.3444123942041,16.2372158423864));
#815=CARTESIAN_POINT('',(22.8338493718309,-13.3774110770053,16.266517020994));
#816=CARTESIAN_POINT('',(22.8818509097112,-13.4463488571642,16.3229161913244));
#817=CARTESIAN_POINT('',(22.9050635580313,-13.4822897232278,16.3500128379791));
#818=CARTESIAN_POINT('',(22.949497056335,-13.557070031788,16.4019242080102));
#819=CARTESIAN_POINT('',(22.9707144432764,-13.5959143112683,16.426734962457));
#820=CARTESIAN_POINT('',(23.0106619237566,-13.6762241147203,16.4739503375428));
#821=CARTESIAN_POINT('',(23.0293925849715,-13.7176890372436,16.4963555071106));
#822=CARTESIAN_POINT('',(23.0813610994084,-13.8460315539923,16.5601063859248));
#823=CARTESIAN_POINT('',(23.1102212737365,-13.9366043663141,16.5978136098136));
#824=CARTESIAN_POINT('',(23.1532386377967,-14.1242157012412,16.6637293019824));
#825=CARTESIAN_POINT('',(23.1674240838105,-14.2212414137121,16.6919559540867));
#826=CARTESIAN_POINT('',(23.1790330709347,-14.4118601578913,16.738481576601));
#827=CARTESIAN_POINT('',(23.1774906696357,-14.5052636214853,16.7573084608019));
#828=CARTESIAN_POINT('',(23.159482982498,-14.6918501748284,16.788731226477));
#829=CARTESIAN_POINT('',(23.1429983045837,-14.7850328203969,16.8013189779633));
#830=CARTESIAN_POINT('',(23.1065553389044,-14.9247853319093,16.8164830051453));
#831=CARTESIAN_POINT('',(23.091906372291,-14.9726027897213,16.8209806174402));
#832=CARTESIAN_POINT('',(23.0585863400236,-15.0669463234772,16.8286067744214));
#833=CARTESIAN_POINT('',(23.0399149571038,-15.1134722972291,16.8317352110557));
#834=CARTESIAN_POINT('',(22.9986839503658,-15.2048196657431,16.8367062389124));
#835=CARTESIAN_POINT('',(22.9761254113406,-15.2496415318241,16.8385491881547));
#836=CARTESIAN_POINT('',(22.9272908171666,-15.3372448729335,16.8409955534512));
#837=CARTESIAN_POINT('',(22.9010149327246,-15.3800264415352,16.8415990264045));
#838=CARTESIAN_POINT('',(22.8729664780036,-15.4216152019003,16.8416052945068));
#839=B_SPLINE_CURVE_WITH_KNOTS('',3,(#813,#814,#815,#816,#817,#818,#819,#820,#821,#822,#823,
#824,#825,#826,#827,#828,#829,#830,#831,#832,#833,#834,#835,#836,#837,#838),.UNSPECIFIED.,.F.,
.F.,(4,2,2,2,2,2,2,2,2,2,2,2,4),(0.,0.151680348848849,0.303452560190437,0.455483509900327,
0.607479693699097,0.912487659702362,1.21690723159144,1.50144834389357,1.78635926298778,
1.93683332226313,2.08731925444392,2.23776325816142,2.38820035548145),.UNSPECIFIED.);
#840=EDGE_CURVE('E455',#810,#782,#839,.T.);
#841=ORIENTED_EDGE('',*,*,#840,.T.);
#842=EDGE_LOOP('',(#784,#785,#793,#812,#841));
#843=FACE_BOUND('',#842,.T.);
#844=ADVANCED_FACE('F1123',(#843),#776,.F.);
#845=CARTESIAN_POINT('',(0.,0.,0.));
#846=DIRECTION('',(0.,0.,-1.));
#847=DIRECTION('',(0.,1.,0.));
#848=AXIS2_PLACEMENT_3D('',#845,#846,#847);
#849=CYLINDRICAL_SURFACE('',#848,27.5862068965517);
#850=DIRECTION('',(0.,0.,-1.));
#851=VECTOR('',#850,1.);
#852=CARTESIAN_POINT('',(-22.8729664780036,-15.4216152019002,0.));
#853=LINE('',#852,#851);
#854=CARTESIAN_POINT('',(-22.8729664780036,-15.4216152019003,16.8416052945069));
#855=VERTEX_POINT('',#854);
#856=EDGE_CURVE('E712',#487,#855,#853,.T.);
#857=ORIENTED_EDGE('',*,*,#856,.F.);
#858=ORIENTED_EDGE('',*,*,#488,.F.);
#859=ORIENTED_EDGE('',*,*,#783,.F.);
#860=CARTESIAN_POINT('',(0.,0.,16.8416052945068));
#861=DIRECTION('',(0.,0.,-1.));
#862=DIRECTION('',(0.,1.,0.));
#863=AXIS2_PLACEMENT_3D('',#860,#861,#862);
#864=CIRCLE('',#863,27.5862068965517);
#865=EDGE_CURVE('E423',#782,#855,#864,.T.);
#866=ORIENTED_EDGE('',*,*,#865,.T.);
#867=EDGE_LOOP('',(#857,#858,#859,#866));
#868=FACE_BOUND('',#867,.T.);
#869=ADVANCED_FACE('F572',(#868),#849,.F.);
#870=CARTESIAN_POINT('',(-21.3989308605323,-14.4277777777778,0.));
#871=DIRECTION('',(0.,0.,-1.));
#872=DIRECTION('',(0.,1.,0.));
#873=AXIS2_PLACEMENT_3D('',#870,#871,#872);
#874=CYLINDRICAL_SURFACE('',#873,1.77777777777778);
#875=CARTESIAN_POINT('',(-21.3989308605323,-12.65,14.9782932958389));
#876=CARTESIAN_POINT('',(-21.4610547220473,-12.6500133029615,15.0212499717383));
#877=CARTESIAN_POINT('',(-21.5224885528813,-12.6532558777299,15.0650938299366));
#878=CARTESIAN_POINT('',(-21.6436537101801,-12.6658686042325,15.1541543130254));
#879=CARTESIAN_POINT('',(-21.7033861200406,-12.6752347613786,15.1993700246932));
#880=CARTESIAN_POINT('',(-21.8797542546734,-12.7120473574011,15.3366260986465));
#881=CARTESIAN_POINT('',(-21.9934694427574,-12.7482069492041,15.4302116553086));
#882=CARTESIAN_POINT('',(-22.2118338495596,-12.8422167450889,15.6198135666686));
#883=CARTESIAN_POINT('',(-22.3163555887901,-12.9003261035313,15.7158456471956));
#884=CARTESIAN_POINT('',(-22.5121828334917,-13.0366120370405,15.9067871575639));
#885=CARTESIAN_POINT('',(-22.6035183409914,-13.1147418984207,16.0016986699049));
#886=CARTESIAN_POINT('',(-22.7204383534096,-13.2376134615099,16.132494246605));
#887=CARTESIAN_POINT('',(-22.7527823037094,-13.2745232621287,16.169864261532));
#888=CARTESIAN_POINT('',(-22.7836981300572,-13.3129175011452,16.2068560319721));
#889=B_SPLINE_CURVE_WITH_KNOTS('',3,(#875,#876,#877,#878,#879,#880,#881,#882,#883,#884,#885,
#886,#887,#888),.UNSPECIFIED.,.F.,.F.,(4,2,2,2,2,2,4),(0.,0.226402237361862,0.452656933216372,
0.905496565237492,1.36385890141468,1.82116133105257,2.00607794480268),.UNSPECIFIED.);
#890=CARTESIAN_POINT('',(-21.3989308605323,-12.65,14.9782932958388));
#891=VERTEX_POINT('',#890);
#892=CARTESIAN_POINT('',(-22.7836981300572,-13.3129175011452,16.2068560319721));
#893=VERTEX_POINT('',#892);
#894=EDGE_CURVE('E586',#891,#893,#889,.T.);
#895=ORIENTED_EDGE('',*,*,#894,.F.);
#896=DIRECTION('',(0.,0.,-1.));
#897=VECTOR('',#896,1.);
#898=CARTESIAN_POINT('',(-21.3989308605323,-12.65,0.));
#899=LINE('',#898,#897);
#900=EDGE_CURVE('E567',#524,#891,#899,.T.);
#901=ORIENTED_EDGE('',*,*,#900,.F.);
#902=ORIENTED_EDGE('',*,*,#525,.F.);
#903=ORIENTED_EDGE('',*,*,#856,.T.);
#904=CARTESIAN_POINT('',(-22.8729664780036,-15.4216152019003,16.8416052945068));
#905=CARTESIAN_POINT('',(-22.8996763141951,-15.3820095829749,16.8416001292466));
#906=CARTESIAN_POINT('',(-22.9247796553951,-15.3413229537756,16.8410523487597));
#907=CARTESIAN_POINT('',(-22.9716219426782,-15.2580863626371,16.8388345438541));
#908=CARTESIAN_POINT('',(-22.9933608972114,-15.2155364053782,16.8371645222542));
#909=CARTESIAN_POINT('',(-23.0333210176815,-15.1288762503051,16.8326654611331));
#910=CARTESIAN_POINT('',(-23.0515425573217,-15.0847662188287,16.8298365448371));
#911=CARTESIAN_POINT('',(-23.0843560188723,-14.9953240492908,16.8229501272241));
#912=CARTESIAN_POINT('',(-23.0989480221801,-14.9499919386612,16.8188926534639));
#913=CARTESIAN_POINT('',(-23.137159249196,-14.8125802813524,16.8047323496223));
#914=CARTESIAN_POINT('',(-23.1552164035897,-14.7190794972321,16.7926413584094));
#915=CARTESIAN_POINT('',(-23.1761893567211,-14.5314973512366,16.7622317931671));
#916=CARTESIAN_POINT('',(-23.179114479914,-14.4374163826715,16.7439170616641));
#917=CARTESIAN_POINT('',(-23.1704438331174,-14.2525266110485,16.700196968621));
#918=CARTESIAN_POINT('',(-23.1589847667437,-14.1616953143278,16.6748601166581));
#919=CARTESIAN_POINT('',(-23.1231190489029,-13.9853178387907,16.6161578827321));
#920=CARTESIAN_POINT('',(-23.0987087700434,-13.8997731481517,16.5827902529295));
#921=CARTESIAN_POINT('',(-23.0391732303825,-13.7366680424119,16.5076734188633));
#922=CARTESIAN_POINT('',(-23.0040636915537,-13.6590961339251,16.4659365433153));
#923=CARTESIAN_POINT('',(-22.9258673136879,-13.5135698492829,16.3741900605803));
#924=CARTESIAN_POINT('',(-22.8827885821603,-13.4456058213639,16.3241888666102));
#925=CARTESIAN_POINT('',(-22.8284679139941,-13.3708287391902,16.2601022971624));
#926=CARTESIAN_POINT('',(-22.8196226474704,-13.3589721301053,16.2496364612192));
#927=CARTESIAN_POINT('',(-22.8017762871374,-13.3356547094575,16.228444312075));
#928=CARTESIAN_POINT('',(-22.7927754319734,-13.3241933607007,16.2177183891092));
#929=CARTESIAN_POINT('',(-22.7836981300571,-13.3129175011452,16.2068560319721));
#930=B_SPLINE_CURVE_WITH_KNOTS('',3,(#904,#905,#906,#907,#908,#909,#910,#911,#912,#913,#914,
#915,#916,#917,#918,#919,#920,#921,#922,#923,#924,#925,#926,#927,#928,#929),.UNSPECIFIED.,.F.,
.F.,(4,2,2,2,2,2,2,2,2,2,2,2,4),(0.,0.143266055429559,0.286531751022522,0.429782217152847,
0.573029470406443,0.859504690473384,1.1458033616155,1.42940160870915,1.71307932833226,
1.99634219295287,2.27931844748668,2.33367800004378,2.38796050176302),.UNSPECIFIED.);
#931=EDGE_CURVE('E579',#855,#893,#930,.T.);
#932=ORIENTED_EDGE('',*,*,#931,.T.);
#933=EDGE_LOOP('',(#895,#901,#902,#903,#932));
#934=FACE_BOUND('',#933,.T.);
#935=ADVANCED_FACE('F569',(#934),#874,.F.);
#936=CARTESIAN_POINT('',(-21.3989308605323,-12.65,0.));
#937=DIRECTION('',(0.,1.,0.));
#938=DIRECTION('',(-1.,0.,0.));
#939=AXIS2_PLACEMENT_3D('',#936,#937,#938);
#940=PLANE('',#939);
#941=ORIENTED_EDGE('',*,*,#792,.T.);
#942=ORIENTED_EDGE('',*,*,#578,.T.);
#943=ORIENTED_EDGE('',*,*,#900,.T.);
#944=CARTESIAN_POINT('',(21.3989308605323,-12.65,14.9782932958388));
#945=CARTESIAN_POINT('',(21.0186384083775,-12.65,14.7153958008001));
#946=CARTESIAN_POINT('',(20.6375100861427,-12.65,14.4537006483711));
#947=CARTESIAN_POINT('',(19.8733151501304,-12.65,13.9331313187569));
#948=CARTESIAN_POINT('',(19.4902484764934,-12.65,13.6742572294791));
#949=CARTESIAN_POINT('',(18.7216473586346,-12.65,13.1595708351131));
#950=CARTESIAN_POINT('',(18.3361112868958,-12.65,12.903760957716));
#951=CARTESIAN_POINT('',(17.5625467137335,-12.65,12.39594076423));
#952=CARTESIAN_POINT('',(17.1745182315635,-12.65,12.1439304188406));
#953=CARTESIAN_POINT('',(16.3842582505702,-12.65,11.6370818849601));
#954=CARTESIAN_POINT('',(15.9819422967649,-12.65,11.3823751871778));
#955=CARTESIAN_POINT('',(15.1738233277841,-12.65,10.8785548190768));
#956=CARTESIAN_POINT('',(14.7680203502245,-12.65,10.629441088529));
#957=CARTESIAN_POINT('',(13.9524762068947,-12.65,10.1379618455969));
#958=CARTESIAN_POINT('',(13.5427360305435,-12.65,9.89559469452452));
#959=CARTESIAN_POINT('',(12.7185869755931,-12.65,9.41892431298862));
#960=CARTESIAN_POINT('',(12.3041781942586,-12.65,9.18462091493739));
#961=CARTESIAN_POINT('',(11.5582035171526,-12.65,8.77436341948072));
#962=CARTESIAN_POINT('',(11.2276601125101,-12.65,8.59655215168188));
#963=CARTESIAN_POINT('',(10.562819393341,-12.65,8.24809998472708));
#964=CARTESIAN_POINT('',(10.228522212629,-12.65,8.07745883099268));
#965=CARTESIAN_POINT('',(9.55558868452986,-12.65,7.74454301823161));
#966=CARTESIAN_POINT('',(9.21695046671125,-12.65,7.58227212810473));
#967=CARTESIAN_POINT('',(8.53505086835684,-12.65,7.26771912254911));
#968=CARTESIAN_POINT('',(8.19178952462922,-12.65,7.11543692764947));
#969=CARTESIAN_POINT('',(7.50356641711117,-12.65,6.82410462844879));
#970=CARTESIAN_POINT('',(7.15865281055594,-12.65,6.68494128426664));
#971=CARTESIAN_POINT('',(6.46356738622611,-12.65,6.42029618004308));
#972=CARTESIAN_POINT('',(6.1133953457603,-12.65,6.29481500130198));
#973=CARTESIAN_POINT('',(5.40793811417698,-12.65,6.06001430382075));
#974=CARTESIAN_POINT('',(5.05265702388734,-12.65,5.95068253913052));
#975=CARTESIAN_POINT('',(4.33688412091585,-12.65,5.75067661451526));
#976=CARTESIAN_POINT('',(3.97639322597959,-12.65,5.65999921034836));
#977=CARTESIAN_POINT('',(3.37230197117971,-12.65,5.52673921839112));
#978=CARTESIAN_POINT('',(3.13000345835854,-12.65,5.47822155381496));
#979=CARTESIAN_POINT('',(2.64360354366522,-12.65,5.39131209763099));
#980=CARTESIAN_POINT('',(2.39950229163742,-12.65,5.35291947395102));
#981=CARTESIAN_POINT('',(1.90987765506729,-12.65,5.28689267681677));
#982=CARTESIAN_POINT('',(1.66435447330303,-12.65,5.25925700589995));
#983=CARTESIAN_POINT('',(1.17229451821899,-12.65,5.21522541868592));
#984=CARTESIAN_POINT('',(0.92575773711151,-12.65,5.19882958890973));
#985=CARTESIAN_POINT('',(0.432687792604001,-12.65,5.17760598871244));
#986=CARTESIAN_POINT('',(0.186155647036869,-12.65,5.17275469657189));
#987=CARTESIAN_POINT('',(-0.306860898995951,-12.65,5.17464369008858));
#988=CARTESIAN_POINT('',(-0.553345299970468,-12.65,5.18138384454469));
#989=CARTESIAN_POINT('',(-1.04575797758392,-12.65,5.2063292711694));
#990=CARTESIAN_POINT('',(-1.29168619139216,-12.65,5.2245357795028));
#991=CARTESIAN_POINT('',(-1.78246843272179,-12.65,5.27207762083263));
#992=CARTESIAN_POINT('',(-2.02732239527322,-12.65,5.3014136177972));
#993=CARTESIAN_POINT('',(-2.58212830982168,-12.65,5.3801637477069));
#994=CARTESIAN_POINT('',(-2.89161629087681,-12.65,5.43287205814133));
#995=CARTESIAN_POINT('',(-3.50744705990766,-12.65,5.55414172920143));
#996=CARTESIAN_POINT('',(-3.81378955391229,-12.65,5.62270455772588));
#997=CARTESIAN_POINT('',(-4.7277144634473,-12.65,5.8499289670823));
#998=CARTESIAN_POINT('',(-5.33003314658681,-12.65,6.03010213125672));
#999=CARTESIAN_POINT('',(-6.22571394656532,-12.65,6.33518139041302));
#1000=CARTESIAN_POINT('',(-6.52497577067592,-12.65,6.44353339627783));
#1001=CARTESIAN_POINT('',(-7.11970616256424,-12.65,6.67026158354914));
#1002=CARTESIAN_POINT('',(-7.41517471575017,-12.65,6.78863780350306));
#1003=CARTESIAN_POINT('',(-8.00237682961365,-12.65,7.03404345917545));
#1004=CARTESIAN_POINT('',(-8.29411139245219,-12.65,7.16107051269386));
#1005=CARTESIAN_POINT('',(-8.87418813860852,-12.65,7.42266411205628));
#1006=CARTESIAN_POINT('',(-9.16253014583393,-12.65,7.55723104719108));
#1007=CARTESIAN_POINT('',(-9.988206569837,-12.65,7.95405711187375));
#1008=CARTESIAN_POINT('',(-10.5215789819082,-12.65,8.22456823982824));
#1009=CARTESIAN_POINT('',(-11.5789925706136,-12.65,8.7832668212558));
#1010=CARTESIAN_POINT('',(-12.103032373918,-12.65,9.07145684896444));
#1011=CARTESIAN_POINT('',(-13.1437615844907,-12.65,9.66184956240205));
#1012=CARTESIAN_POINT('',(-13.66044385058,-12.65,9.96406479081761));
#1013=CARTESIAN_POINT('',(-14.6872579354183,-12.65,10.579318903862));
#1014=CARTESIAN_POINT('',(-15.1973901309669,-12.65,10.8923571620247));
#1015=CARTESIAN_POINT('',(-16.1878766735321,-12.65,11.5118608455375));
#1016=CARTESIAN_POINT('',(-16.668485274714,-12.65,11.8179208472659));
#1017=CARTESIAN_POINT('',(-17.6255631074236,-12.65,12.4364605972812));
#1018=CARTESIAN_POINT('',(-18.1020322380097,-12.65,12.7489405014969));
#1019=CARTESIAN_POINT('',(-19.0502926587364,-12.65,13.3784114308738));
#1020=CARTESIAN_POINT('',(-19.5220925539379,-12.65,13.6953895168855));
#1021=CARTESIAN_POINT('',(-20.4626557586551,-12.65,14.3337448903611));
#1022=CARTESIAN_POINT('',(-20.9314192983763,-12.65,14.6551218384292));
#1023=CARTESIAN_POINT('',(-21.3989308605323,-12.65,14.9782932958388));
#1024=B_SPLINE_CURVE_WITH_KNOTS('',3,(#944,#945,#946,#947,#948,#949,#950,#951,#952,#953,#954,
#955,#956,#957,#958,#959,#960,#961,#962,#963,#964,#965,#966,#967,#968,#969,#970,#971,#972,#973,
#974,#975,#976,#977,#978,#979,#980,#981,#982,#983,#984,#985,#986,#987,#988,#989,#990,#991,#992,
#993,#994,#995,#996,#997,#998,#999,#1000,#1001,#1002,#1003,#1004,#1005,#1006,#1007,#1008,#1009,
#1010,#1011,#1012,#1013,#1014,#1015,#1016,#1017,#1018,#1019,#1020,#1021,#1022,#1023),
.UNSPECIFIED.,.F.,.F.,(4,2,2,2,2,2,2,2,2,2,2,2,2,2,2,2,2,2,2,2,2,2,2,2,2,2,2,2,2,2,2,2,2,2,2,2,
2,2,2,4),(0.,1.38695581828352,2.77395473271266,4.16198816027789,5.55001087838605,
6.9784691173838,8.40691196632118,9.83500477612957,11.2630678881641,12.3889979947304,
13.5148880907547,14.6412807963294,15.7676645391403,16.8832080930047,17.9987990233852,
19.1135396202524,20.2280861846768,20.969223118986,21.7102991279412,22.4512719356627,
23.1922504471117,23.9317179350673,24.6711770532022,25.4107159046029,26.1502988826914,
27.0916477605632,28.0330838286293,29.9164428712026,30.871154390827,31.8258695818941,
32.7803229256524,33.7348255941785,35.5284895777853,37.3224153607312,39.11797758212,
40.9134360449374,42.6227370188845,44.3320795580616,46.0372310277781,47.7422516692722),.UNSPECIFIED.);
#1025=EDGE_CURVE('E593',#791,#891,#1024,.T.);
#1026=ORIENTED_EDGE('',*,*,#1025,.F.);
#1027=EDGE_LOOP('',(#941,#942,#943,#1026));
#1028=FACE_BOUND('',#1027,.T.);
#1029=ADVANCED_FACE('F531',(#1028),#940,.F.);
#1030=CARTESIAN_POINT('',(-5.75,0.,20.));
#1031=DIRECTION('',(0.,0.,1.));
#1032=DIRECTION('',(-1.,0.,0.));
#1033=AXIS2_PLACEMENT_3D('',#1030,#1031,#1032);
#1034=PLANE('',#1033);
#1035=ORIENTED_EDGE('',*,*,#589,.T.);
#1036=EDGE_LOOP('',(#1035));
#1037=FACE_BOUND('',#1036,.T.);
#1038=ADVANCED_FACE('F486',(#1037),#1034,.T.);
#1039=CARTESIAN_POINT('',(21.3989308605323,14.4277777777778,0.));
#1040=DIRECTION('',(0.,0.,-1.));
#1041=DIRECTION('',(0.,1.,0.));
#1042=AXIS2_PLACEMENT_3D('',#1039,#1040,#1041);
#1043=CYLINDRICAL_SURFACE('',#1042,1.77777777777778);
#1044=DIRECTION('',(0.,0.,-1.));
#1045=VECTOR('',#1044,1.);
#1046=CARTESIAN_POINT('',(22.8729664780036,15.4216152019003,0.));
#1047=LINE('',#1046,#1045);
#1048=CARTESIAN_POINT('',(22.8729664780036,15.4216152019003,16.8416052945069));
#1049=VERTEX_POINT('',#1048);
#1050=EDGE_CURVE('E512',#1049,#627,#1047,.F.);
#1051=ORIENTED_EDGE('',*,*,#1050,.F.);
#1052=CARTESIAN_POINT('',(22.8729664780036,15.4216152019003,16.8416052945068));
#1053=CARTESIAN_POINT('',(22.8996763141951,15.3820095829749,16.8416001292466));
#1054=CARTESIAN_POINT('',(22.9247796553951,15.3413229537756,16.8410523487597));
#1055=CARTESIAN_POINT('',(22.9716219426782,15.2580863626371,16.8388345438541));
#1056=CARTESIAN_POINT('',(22.9933608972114,15.2155364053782,16.8371645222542));
#1057=CARTESIAN_POINT('',(23.0333210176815,15.1288762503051,16.8326654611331));
#1058=CARTESIAN_POINT('',(23.0515425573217,15.0847662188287,16.8298365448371));
#1059=CARTESIAN_POINT('',(23.0843560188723,14.9953240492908,16.8229501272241));
#1060=CARTESIAN_POINT('',(23.0989480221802,14.9499919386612,16.8188926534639));
#1061=CARTESIAN_POINT('',(23.1371592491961,14.8125802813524,16.8047323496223));
#1062=CARTESIAN_POINT('',(23.1552164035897,14.7190794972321,16.7926413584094));
#1063=CARTESIAN_POINT('',(23.176189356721,14.5314973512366,16.7622317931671));
#1064=CARTESIAN_POINT('',(23.179114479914,14.4374163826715,16.7439170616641));
#1065=CARTESIAN_POINT('',(23.1704438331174,14.2525266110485,16.700196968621));
#1066=CARTESIAN_POINT('',(23.1589847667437,14.1616953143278,16.6748601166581));
#1067=CARTESIAN_POINT('',(23.1231190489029,13.9853178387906,16.6161578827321));
#1068=CARTESIAN_POINT('',(23.0987087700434,13.8997731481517,16.5827902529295));
#1069=CARTESIAN_POINT('',(23.0391732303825,13.7366680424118,16.5076734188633));
#1070=CARTESIAN_POINT('',(23.0040636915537,13.6590961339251,16.4659365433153));
#1071=CARTESIAN_POINT('',(22.9258673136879,13.5135698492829,16.3741900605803));
#1072=CARTESIAN_POINT('',(22.8827885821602,13.4456058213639,16.3241888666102));
#1073=CARTESIAN_POINT('',(22.8284679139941,13.3708287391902,16.2601022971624));
#1074=CARTESIAN_POINT('',(22.8196226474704,13.3589721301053,16.2496364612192));
#1075=CARTESIAN_POINT('',(22.8017762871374,13.3356547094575,16.228444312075));
#1076=CARTESIAN_POINT('',(22.7927754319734,13.3241933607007,16.2177183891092));
#1077=CARTESIAN_POINT('',(22.7836981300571,13.3129175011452,16.2068560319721));
#1078=B_SPLINE_CURVE_WITH_KNOTS('',3,(#1052,#1053,#1054,#1055,#1056,#1057,#1058,#1059,#1060,
#1061,#1062,#1063,#1064,#1065,#1066,#1067,#1068,#1069,#1070,#1071,#1072,#1073,#1074,#1075,#1076,
#1077),.UNSPECIFIED.,.F.,.F.,(4,2,2,2,2,2,2,2,2,2,2,2,4),(0.,0.143266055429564,
0.286531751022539,0.429782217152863,0.573029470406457,0.859504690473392,1.1458033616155,
1.42940160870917,1.71307932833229,1.99634219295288,2.27931844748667,2.33367800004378,
2.38796050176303),.UNSPECIFIED.);
#1079=CARTESIAN_POINT('',(22.7836981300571,13.3129175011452,16.2068560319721));
#1080=VERTEX_POINT('',#1079);
#1081=EDGE_CURVE('E463',#1049,#1080,#1078,.T.);
#1082=ORIENTED_EDGE('',*,*,#1081,.T.);
#1083=CARTESIAN_POINT('',(21.3989308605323,12.65,14.9782932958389));
#1084=CARTESIAN_POINT('',(21.4610547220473,12.6500133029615,15.0212499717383));
#1085=CARTESIAN_POINT('',(21.5224885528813,12.6532558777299,15.0650938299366));
#1086=CARTESIAN_POINT('',(21.6436537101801,12.6658686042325,15.1541543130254));
#1087=CARTESIAN_POINT('',(21.7033861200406,12.6752347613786,15.1993700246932));
#1088=CARTESIAN_POINT('',(21.8797542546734,12.7120473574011,15.3366260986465));
#1089=CARTESIAN_POINT('',(21.9934694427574,12.7482069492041,15.4302116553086));
#1090=CARTESIAN_POINT('',(22.2118338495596,12.8422167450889,15.6198135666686));
#1091=CARTESIAN_POINT('',(22.3163555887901,12.9003261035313,15.7158456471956));
#1092=CARTESIAN_POINT('',(22.5121828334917,13.0366120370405,15.9067871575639));
#1093=CARTESIAN_POINT('',(22.6035183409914,13.1147418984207,16.0016986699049));
#1094=CARTESIAN_POINT('',(22.7204383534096,13.2376134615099,16.132494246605));
#1095=CARTESIAN_POINT('',(22.7527823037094,13.2745232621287,16.169864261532));
#1096=CARTESIAN_POINT('',(22.7836981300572,13.3129175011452,16.2068560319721));
#1097=B_SPLINE_CURVE_WITH_KNOTS('',3,(#1083,#1084,#1085,#1086,#1087,#1088,#1089,#1090,#1091,
#1092,#1093,#1094,#1095,#1096),.UNSPECIFIED.,.F.,.F.,(4,2,2,2,2,2,4),(0.,0.226402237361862,
0.452656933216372,0.905496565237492,1.36385890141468,1.82116133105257,2.00607794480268),.UNSPECIFIED.);
#1098=CARTESIAN_POINT('',(21.3989308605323,12.65,14.9782932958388));
#1099=VERTEX_POINT('',#1098);
#1100=EDGE_CURVE('E494',#1099,#1080,#1097,.T.);
#1101=ORIENTED_EDGE('',*,*,#1100,.F.);
#1102=DIRECTION('',(0.,0.,-1.));
#1103=VECTOR('',#1102,1.);
#1104=CARTESIAN_POINT('',(21.3989308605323,12.65,0.));
#1105=LINE('',#1104,#1103);
#1106=EDGE_CURVE('E665',#629,#1099,#1105,.T.);
#1107=ORIENTED_EDGE('',*,*,#1106,.F.);
#1108=ORIENTED_EDGE('',*,*,#630,.F.);
#1109=EDGE_LOOP('',(#1051,#1082,#1101,#1107,#1108));
#1110=FACE_BOUND('',#1109,.T.);
#1111=ADVANCED_FACE('F480',(#1110),#1043,.F.);
#1112=CARTESIAN_POINT('',(21.3989308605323,12.65,0.));
#1113=DIRECTION('',(0.,-1.,0.));
#1114=DIRECTION('',(1.,0.,0.));
#1115=AXIS2_PLACEMENT_3D('',#1112,#1113,#1114);
#1116=PLANE('',#1115);
#1117=ORIENTED_EDGE('',*,*,#1106,.T.);
#1118=CARTESIAN_POINT('',(-21.3989308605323,12.65,14.9782932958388));
#1119=CARTESIAN_POINT('',(-21.0186384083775,12.65,14.7153958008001));
#1120=CARTESIAN_POINT('',(-20.6375100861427,12.65,14.4537006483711));
#1121=CARTESIAN_POINT('',(-19.8733151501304,12.65,13.9331313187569));
#1122=CARTESIAN_POINT('',(-19.4902484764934,12.65,13.6742572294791));
#1123=CARTESIAN_POINT('',(-18.7216473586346,12.65,13.1595708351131));
#1124=CARTESIAN_POINT('',(-18.3361112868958,12.65,12.903760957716));
#1125=CARTESIAN_POINT('',(-17.5625467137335,12.65,12.39594076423));
#1126=CARTESIAN_POINT('',(-17.1745182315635,12.65,12.1439304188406));
#1127=CARTESIAN_POINT('',(-16.3842582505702,12.65,11.6370818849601));
#1128=CARTESIAN_POINT('',(-15.9819422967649,12.65,11.3823751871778));
#1129=CARTESIAN_POINT('',(-15.1738233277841,12.65,10.8785548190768));
#1130=CARTESIAN_POINT('',(-14.7680203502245,12.65,10.629441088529));
#1131=CARTESIAN_POINT('',(-13.9524762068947,12.65,10.1379618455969));
#1132=CARTESIAN_POINT('',(-13.5427360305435,12.65,9.89559469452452));
#1133=CARTESIAN_POINT('',(-12.7185869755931,12.65,9.41892431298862));
#1134=CARTESIAN_POINT('',(-12.3041781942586,12.65,9.18462091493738));
#1135=CARTESIAN_POINT('',(-11.5582035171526,12.65,8.77436341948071));
#1136=CARTESIAN_POINT('',(-11.2276601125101,12.65,8.59655215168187));
#1137=CARTESIAN_POINT('',(-10.562819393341,12.65,8.24809998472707));
#1138=CARTESIAN_POINT('',(-10.228522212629,12.65,8.07745883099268));
#1139=CARTESIAN_POINT('',(-9.55558868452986,12.65,7.7445430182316));
#1140=CARTESIAN_POINT('',(-9.21695046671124,12.65,7.58227212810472));
#1141=CARTESIAN_POINT('',(-8.53505086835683,12.65,7.26771912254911));
#1142=CARTESIAN_POINT('',(-8.19178952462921,12.65,7.11543692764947));
#1143=CARTESIAN_POINT('',(-7.50356641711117,12.65,6.8241046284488));
#1144=CARTESIAN_POINT('',(-7.15865281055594,12.65,6.68494128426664));
#1145=CARTESIAN_POINT('',(-6.4635673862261,12.65,6.42029618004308));
#1146=CARTESIAN_POINT('',(-6.1133953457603,12.65,6.29481500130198));
#1147=CARTESIAN_POINT('',(-5.40793811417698,12.65,6.06001430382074));
#1148=CARTESIAN_POINT('',(-5.05265702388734,12.65,5.95068253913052));
#1149=CARTESIAN_POINT('',(-4.33688412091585,12.65,5.75067661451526));
#1150=CARTESIAN_POINT('',(-3.97639322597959,12.65,5.65999921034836));
#1151=CARTESIAN_POINT('',(-3.37230197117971,12.65,5.52673921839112));
#1152=CARTESIAN_POINT('',(-3.13000345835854,12.65,5.47822155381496));
#1153=CARTESIAN_POINT('',(-2.64360354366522,12.65,5.39131209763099));
#1154=CARTESIAN_POINT('',(-2.39950229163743,12.65,5.35291947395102));
#1155=CARTESIAN_POINT('',(-1.90987765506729,12.65,5.28689267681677));
#1156=CARTESIAN_POINT('',(-1.66435447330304,12.65,5.25925700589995));
#1157=CARTESIAN_POINT('',(-1.17229451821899,12.65,5.21522541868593));
#1158=CARTESIAN_POINT('',(-0.925757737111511,12.65,5.19882958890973));
#1159=CARTESIAN_POINT('',(-0.432687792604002,12.65,5.17760598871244));
#1160=CARTESIAN_POINT('',(-0.18615564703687,12.65,5.17275469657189));
#1161=CARTESIAN_POINT('',(0.30686089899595,12.65,5.17464369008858));
#1162=CARTESIAN_POINT('',(0.553345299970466,12.65,5.18138384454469));
#1163=CARTESIAN_POINT('',(1.04575797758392,12.65,5.2063292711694));
#1164=CARTESIAN_POINT('',(1.29168619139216,12.65,5.2245357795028));
#1165=CARTESIAN_POINT('',(1.78246843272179,12.65,5.27207762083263));
#1166=CARTESIAN_POINT('',(2.02732239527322,12.65,5.30141361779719));
#1167=CARTESIAN_POINT('',(2.58212830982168,12.65,5.3801637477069));
#1168=CARTESIAN_POINT('',(2.89161629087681,12.65,5.43287205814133));
#1169=CARTESIAN_POINT('',(3.50744705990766,12.65,5.55414172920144));
#1170=CARTESIAN_POINT('',(3.81378955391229,12.65,5.62270455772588));
#1171=CARTESIAN_POINT('',(4.7277144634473,12.65,5.8499289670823));
#1172=CARTESIAN_POINT('',(5.33003314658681,12.65,6.03010213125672));
#1173=CARTESIAN_POINT('',(6.22571394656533,12.65,6.33518139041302));
#1174=CARTESIAN_POINT('',(6.52497577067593,12.65,6.44353339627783));
#1175=CARTESIAN_POINT('',(7.11970616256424,12.65,6.67026158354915));
#1176=CARTESIAN_POINT('',(7.41517471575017,12.65,6.78863780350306));
#1177=CARTESIAN_POINT('',(8.00237682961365,12.65,7.03404345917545));
#1178=CARTESIAN_POINT('',(8.29411139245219,12.65,7.16107051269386));
#1179=CARTESIAN_POINT('',(8.87418813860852,12.65,7.42266411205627));
#1180=CARTESIAN_POINT('',(9.16253014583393,12.65,7.55723104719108));
#1181=CARTESIAN_POINT('',(9.98820656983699,12.65,7.95405711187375));
#1182=CARTESIAN_POINT('',(10.5215789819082,12.65,8.22456823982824));
#1183=CARTESIAN_POINT('',(11.5789925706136,12.65,8.7832668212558));
#1184=CARTESIAN_POINT('',(12.103032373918,12.65,9.07145684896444));
#1185=CARTESIAN_POINT('',(13.1437615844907,12.65,9.66184956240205));
#1186=CARTESIAN_POINT('',(13.66044385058,12.65,9.96406479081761));
#1187=CARTESIAN_POINT('',(14.6872579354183,12.65,10.579318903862));
#1188=CARTESIAN_POINT('',(15.1973901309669,12.65,10.8923571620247));
#1189=CARTESIAN_POINT('',(16.1878766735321,12.65,11.5118608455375));
#1190=CARTESIAN_POINT('',(16.668485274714,12.65,11.8179208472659));
#1191=CARTESIAN_POINT('',(17.6255631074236,12.65,12.4364605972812));
#1192=CARTESIAN_POINT('',(18.1020322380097,12.65,12.7489405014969));
#1193=CARTESIAN_POINT('',(19.0502926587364,12.65,13.3784114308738));
#1194=CARTESIAN_POINT('',(19.5220925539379,12.65,13.6953895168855));
#1195=CARTESIAN_POINT('',(20.4626557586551,12.65,14.3337448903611));
#1196=CARTESIAN_POINT('',(20.9314192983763,12.65,14.6551218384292));
#1197=CARTESIAN_POINT('',(21.3989308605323,12.65,14.9782932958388));
#1198=B_SPLINE_CURVE_WITH_KNOTS('',3,(#1118,#1119,#1120,#1121,#1122,#1123,#1124,#1125,#1126,
#1127,#1128,#1129,#1130,#1131,#1132,#1133,#1134,#1135,#1136,#1137,#1138,#1139,#1140,#1141,#1142,
#1143,#1144,#1145,#1146,#1147,#1148,#1149,#1150,#1151,#1152,#1153,#1154,#1155,#1156,#1157,#1158,
#1159,#1160,#1161,#1162,#1163,#1164,#1165,#1166,#1167,#1168,#1169,#1170,#1171,#1172,#1173,#1174,
#1175,#1176,#1177,#1178,#1179,#1180,#1181,#1182,#1183,#1184,#1185,#1186,#1187,#1188,#1189,#1190,
#1191,#1192,#1193,#1194,#1195,#1196,#1197),.UNSPECIFIED.,.F.,.F.,(4,2,2,2,2,2,2,2,2,2,2,2,2,2,2,
2,2,2,2,2,2,2,2,2,2,2,2,2,2,2,2,2,2,2,2,2,2,2,2,4),(0.,1.38695581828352,2.77395473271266,
4.1619881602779,5.55001087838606,6.9784691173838,8.40691196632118,9.83500477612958,
11.2630678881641,12.3889979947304,13.5148880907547,14.6412807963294,15.7676645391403,
16.8832080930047,17.9987990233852,19.1135396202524,20.2280861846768,20.969223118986,
21.7102991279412,22.4512719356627,23.1922504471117,23.9317179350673,24.6711770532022,
25.4107159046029,26.1502988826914,27.0916477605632,28.0330838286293,29.9164428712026,
30.871154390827,31.8258695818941,32.7803229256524,33.7348255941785,35.5284895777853,
37.3224153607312,39.11797758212,40.9134360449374,42.6227370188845,44.3320795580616,
46.0372310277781,47.7422516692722),.UNSPECIFIED.);
#1199=CARTESIAN_POINT('',(-21.3989308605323,12.65,14.9782932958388));
#1200=VERTEX_POINT('',#1199);
#1201=EDGE_CURVE('E606',#1200,#1099,#1198,.T.);
#1202=ORIENTED_EDGE('',*,*,#1201,.F.);
#1203=DIRECTION('',(0.,0.,-1.));
#1204=VECTOR('',#1203,1.);
#1205=CARTESIAN_POINT('',(-21.3989308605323,12.65,0.));
#1206=LINE('',#1205,#1204);
#1207=EDGE_CURVE('E1330',#1200,#684,#1206,.F.);
#1208=ORIENTED_EDGE('',*,*,#1207,.T.);
#1209=ORIENTED_EDGE('',*,*,#685,.F.);
#1210=EDGE_LOOP('',(#1117,#1202,#1208,#1209));
#1211=FACE_BOUND('',#1210,.T.);
#1212=ADVANCED_FACE('F485',(#1211),#1116,.F.);
#1213=CARTESIAN_POINT('',(-21.3989308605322,14.4277777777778,0.));
#1214=DIRECTION('',(0.,0.,-1.));
#1215=DIRECTION('',(0.,1.,0.));
#1216=AXIS2_PLACEMENT_3D('',#1213,#1214,#1215);
#1217=CYLINDRICAL_SURFACE('',#1216,1.77777777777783);
#1218=ORIENTED_EDGE('',*,*,#1207,.F.);
#1219=CARTESIAN_POINT('',(-22.7836981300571,13.3129175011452,16.2068560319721));
#1220=CARTESIAN_POINT('',(-22.7459774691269,13.2660802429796,16.1617237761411));
#1221=CARTESIAN_POINT('',(-22.7061736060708,13.2214903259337,16.1160758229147));
#1222=CARTESIAN_POINT('',(-22.6227539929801,13.136930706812,16.0240217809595));
#1223=CARTESIAN_POINT('',(-22.5791393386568,13.096959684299,15.9776159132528));
#1224=CARTESIAN_POINT('',(-22.4426527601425,12.9837735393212,15.8371959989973));
#1225=CARTESIAN_POINT('',(-22.344496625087,12.9177249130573,15.7424058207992));
#1226=CARTESIAN_POINT('',(-22.1302005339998,12.802506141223,15.5470962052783));
#1227=CARTESIAN_POINT('',(-22.0133082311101,12.7547030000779,15.4466024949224));
#1228=CARTESIAN_POINT('',(-21.7698021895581,12.6845298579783,15.2491942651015));
#1229=CARTESIAN_POINT('',(-21.6432295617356,12.6620580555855,15.1522669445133));
#1230=CARTESIAN_POINT('',(-21.4754888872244,12.6512453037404,15.0317500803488));
#1231=CARTESIAN_POINT('',(-21.4373276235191,12.6500033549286,15.0048419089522));
#1232=CARTESIAN_POINT('',(-21.3989308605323,12.65,14.9782932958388));
#1233=B_SPLINE_CURVE_WITH_KNOTS('',3,(#1219,#1220,#1221,#1222,#1223,#1224,#1225,#1226,#1227,
#1228,#1229,#1230,#1231,#1232),.UNSPECIFIED.,.F.,.F.,(4,2,2,2,2,2,4),(0.,0.225422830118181,
0.450781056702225,0.903602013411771,1.38569343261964,1.8658404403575,2.00590562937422),.UNSPECIFIED.);
#1234=CARTESIAN_POINT('',(-22.7836981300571,13.3129175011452,16.2068560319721));
#1235=VERTEX_POINT('',#1234);
#1236=EDGE_CURVE('E511',#1235,#1200,#1233,.T.);
#1237=ORIENTED_EDGE('',*,*,#1236,.F.);
#1238=CARTESIAN_POINT('',(-22.7836981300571,13.3129175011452,16.2068560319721));
#1239=CARTESIAN_POINT('',(-22.8090614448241,13.3444123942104,16.2372158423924));
#1240=CARTESIAN_POINT('',(-22.8338493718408,13.3774110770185,16.2665170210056));
#1241=CARTESIAN_POINT('',(-22.8818509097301,13.4463488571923,16.3229161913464));
#1242=CARTESIAN_POINT('',(-22.9050635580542,13.482289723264,16.3500128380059));
#1243=CARTESIAN_POINT('',(-22.9494970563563,13.5570700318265,16.4019242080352));
#1244=CARTESIAN_POINT('',(-22.9707144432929,13.5959143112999,16.4267349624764));
#1245=CARTESIAN_POINT('',(-23.0106619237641,13.676224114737,16.4739503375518));
#1246=CARTESIAN_POINT('',(-23.0293925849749,13.7176890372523,16.4963555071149));
#1247=CARTESIAN_POINT('',(-23.081361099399,13.8460315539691,16.5601063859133));
#1248=CARTESIAN_POINT('',(-23.1102212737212,13.9366043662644,16.5978136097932));
#1249=CARTESIAN_POINT('',(-23.1532386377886,14.1242157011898,16.6637293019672));
#1250=CARTESIAN_POINT('',(-23.1674240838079,14.2212414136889,16.6919559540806));
#1251=CARTESIAN_POINT('',(-23.1790330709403,14.4118601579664,16.7384815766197));
#1252=CARTESIAN_POINT('',(-23.1774906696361,14.5052636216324,16.7573084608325));
#1253=CARTESIAN_POINT('',(-23.1594829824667,14.6918501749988,16.7887312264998));
#1254=CARTESIAN_POINT('',(-23.1429983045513,14.7850328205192,16.8013189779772));
#1255=CARTESIAN_POINT('',(-23.1065553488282,14.924785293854,16.8164830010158));
#1256=CARTESIAN_POINT('',(-23.0919063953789,14.9726027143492,16.8209806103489));
#1257=CARTESIAN_POINT('',(-23.058586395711,15.0669461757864,16.8286067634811));
#1258=CARTESIAN_POINT('',(-23.0399150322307,15.1134721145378,16.8317351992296));
#1259=CARTESIAN_POINT('',(-22.9986840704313,15.2048194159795,16.8367062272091));
#1260=CARTESIAN_POINT('',(-22.9761255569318,15.24964125,16.8385491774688));
#1261=CARTESIAN_POINT('',(-22.9272910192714,15.3372445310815,16.8409955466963));
#1262=CARTESIAN_POINT('',(-22.9010151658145,15.3800260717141,16.8415990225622));
#1263=CARTESIAN_POINT('',(-22.8729667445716,15.4216148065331,16.8416052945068));
#1264=B_SPLINE_CURVE_WITH_KNOTS('',3,(#1238,#1239,#1240,#1241,#1242,#1243,#1244,#1245,#1246,
#1247,#1248,#1249,#1250,#1251,#1252,#1253,#1254,#1255,#1256,#1257,#1258,#1259,#1260,#1261,#1262,
#1263),.UNSPECIFIED.,.F.,.F.,(4,2,2,2,2,2,2,2,2,2,2,2,4),(0.,0.151680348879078,
0.303452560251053,0.455483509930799,0.607479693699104,0.912487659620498,1.21690723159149,
1.50144834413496,1.78635926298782,1.93683320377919,2.08731901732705,2.23776290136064,
2.38819987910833),.UNSPECIFIED.);
#1265=CARTESIAN_POINT('',(-22.8729667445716,15.4216148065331,16.8416052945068));
#1266=VERTEX_POINT('',#1265);
#1267=EDGE_CURVE('E473',#1235,#1266,#1264,.T.);
#1268=ORIENTED_EDGE('',*,*,#1267,.T.);
#1269=DIRECTION('',(0.,0.,-1.));
#1270=VECTOR('',#1269,1.);
#1271=CARTESIAN_POINT('',(-22.8729667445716,15.4216148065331,0.));
#1272=LINE('',#1271,#1270);
#1273=EDGE_CURVE('E1332',#1266,#721,#1272,.F.);
#1274=ORIENTED_EDGE('',*,*,#1273,.T.);
#1275=ORIENTED_EDGE('',*,*,#722,.F.);
#1276=EDGE_LOOP('',(#1218,#1237,#1268,#1274,#1275));
#1277=FACE_BOUND('',#1276,.T.);
#1278=ADVANCED_FACE('F574',(#1277),#1217,.F.);
#1279=CARTESIAN_POINT('',(0.,0.,0.));
#1280=DIRECTION('',(0.,0.,-1.));
#1281=DIRECTION('',(0.,1.,0.));
#1282=AXIS2_PLACEMENT_3D('',#1279,#1280,#1281);
#1283=CYLINDRICAL_SURFACE('',#1282,27.5862068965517);
#1284=ORIENTED_EDGE('',*,*,#1273,.F.);
#1285=CARTESIAN_POINT('',(0.,0.,16.8416052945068));
#1286=DIRECTION('',(0.,0.,-1.));
#1287=DIRECTION('',(0.,1.,0.));
#1288=AXIS2_PLACEMENT_3D('',#1285,#1286,#1287);
#1289=CIRCLE('',#1288,27.5862068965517);
#1290=EDGE_CURVE('E472',#1266,#1049,#1289,.T.);
#1291=ORIENTED_EDGE('',*,*,#1290,.T.);
#1292=ORIENTED_EDGE('',*,*,#1050,.T.);
#1293=ORIENTED_EDGE('',*,*,#729,.F.);
#1294=EDGE_LOOP('',(#1284,#1291,#1292,#1293));
#1295=FACE_BOUND('',#1294,.T.);
#1296=ADVANCED_FACE('F489',(#1295),#1283,.F.);
#1297=CARTESIAN_POINT('',(0.,0.,33.2));
#1298=DIRECTION('',(0.,0.,-1.));
#1299=DIRECTION('',(0.,1.,0.));
#1300=AXIS2_PLACEMENT_3D('',#1297,#1298,#1299);
#1301=TOROIDAL_SURFACE('',#1300,37.0111162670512,1.8);
#1302=CARTESIAN_POINT('',(0.,0.,33.6658742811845));
#1303=DIRECTION('',(0.,0.,-1.));
#1304=DIRECTION('',(-1.,0.,0.));
#1305=AXIS2_PLACEMENT_3D('',#1302,#1303,#1304);
#1306=CIRCLE('',#1305,38.7497827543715);
#1307=CARTESIAN_POINT('',(-38.7497827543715,0.,33.6658742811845));
#1308=VERTEX_POINT('',#1307);
#1309=EDGE_CURVE('E1337',#1308,#1308,#1306,.T.);
#1310=ORIENTED_EDGE('',*,*,#1309,.F.);
#1311=EDGE_LOOP('',(#1310));
#1312=FACE_BOUND('',#1311,.T.);
#1313=ORIENTED_EDGE('',*,*,#751,.T.);
#1314=ORIENTED_EDGE('',*,*,#767,.T.);
#1315=ORIENTED_EDGE('',*,*,#760,.T.);
#1316=EDGE_LOOP('',(#1313,#1314,#1315));
#1317=FACE_BOUND('',#1316,.T.);
#1318=ADVANCED_FACE('F527',(#1312,#1317),#1301,.T.);
#1319=CARTESIAN_POINT('',(0.,0.,16.2068560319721));
#1320=DIRECTION('',(0.,0.,1.));
#1321=DIRECTION('',(0.,-1.,0.));
#1322=AXIS2_PLACEMENT_3D('',#1319,#1320,#1321);
#1323=CONICAL_SURFACE('',#1322,26.3880782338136,0.89415818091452);
#1324=CARTESIAN_POINT('',(0.,0.,5.05311614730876));
#1325=DIRECTION('',(0.,0.,1.));
#1326=DIRECTION('',(-1.,0.,0.));
#1327=AXIS2_PLACEMENT_3D('',#1324,#1325,#1326);
#1328=CIRCLE('',#1327,12.5);
#1329=CARTESIAN_POINT('',(-12.5,0.,5.05311614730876));
#1330=VERTEX_POINT('',#1329);
#1331=EDGE_CURVE('E9',#1330,#1330,#1328,.F.);
#1332=ORIENTED_EDGE('',*,*,#1331,.F.);
#1333=EDGE_LOOP('',(#1332));
#1334=FACE_BOUND('',#1333,.T.);
#1335=ORIENTED_EDGE('',*,*,#894,.T.);
#1336=CARTESIAN_POINT('',(0.,0.,16.2068560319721));
#1337=DIRECTION('',(0.,0.,-1.));
#1338=DIRECTION('',(0.,1.,0.));
#1339=AXIS2_PLACEMENT_3D('',#1336,#1337,#1338);
#1340=CIRCLE('',#1339,26.3880782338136);
#1341=EDGE_CURVE('E695',#893,#1235,#1340,.T.);
#1342=ORIENTED_EDGE('',*,*,#1341,.T.);
#1343=ORIENTED_EDGE('',*,*,#1236,.T.);
#1344=ORIENTED_EDGE('',*,*,#1201,.T.);
#1345=ORIENTED_EDGE('',*,*,#1100,.T.);
#1346=CARTESIAN_POINT('',(0.,0.,16.2068560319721));
#1347=DIRECTION('',(0.,0.,-1.));
#1348=DIRECTION('',(0.,1.,0.));
#1349=AXIS2_PLACEMENT_3D('',#1346,#1347,#1348);
#1350=CIRCLE('',#1349,26.3880782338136);
#1351=EDGE_CURVE('E471',#1080,#810,#1350,.T.);
#1352=ORIENTED_EDGE('',*,*,#1351,.T.);
#1353=ORIENTED_EDGE('',*,*,#811,.T.);
#1354=ORIENTED_EDGE('',*,*,#1025,.T.);
#1355=EDGE_LOOP('',(#1335,#1342,#1343,#1344,#1345,#1352,#1353,#1354));
#1356=FACE_BOUND('',#1355,.T.);
#1357=ADVANCED_FACE('F430',(#1334,#1356),#1323,.T.);
#1358=CARTESIAN_POINT('',(0.,0.,13.4));
#1359=DIRECTION('',(0.,0.,-1.));
#1360=DIRECTION('',(0.,1.,0.));
#1361=AXIS2_PLACEMENT_3D('',#1358,#1359,#1360);
#1362=TOROIDAL_SURFACE('',#1361,28.6423096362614,3.6);
#1363=ORIENTED_EDGE('',*,*,#1290,.F.);
#1364=ORIENTED_EDGE('',*,*,#1267,.F.);
#1365=ORIENTED_EDGE('',*,*,#1341,.F.);
#1366=ORIENTED_EDGE('',*,*,#931,.F.);
#1367=ORIENTED_EDGE('',*,*,#865,.F.);
#1368=ORIENTED_EDGE('',*,*,#840,.F.);
#1369=ORIENTED_EDGE('',*,*,#1351,.F.);
#1370=ORIENTED_EDGE('',*,*,#1081,.F.);
#1371=EDGE_LOOP('',(#1363,#1364,#1365,#1366,#1367,#1368,#1369,#1370));
#1372=FACE_BOUND('',#1371,.T.);
#1373=CARTESIAN_POINT('',(0.,0.,17.));
#1374=DIRECTION('',(0.,0.,-1.));
#1375=DIRECTION('',(0.,-1.,0.));
#1376=AXIS2_PLACEMENT_3D('',#1373,#1374,#1375);
#1377=CIRCLE('',#1376,28.6423096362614);
#1378=CARTESIAN_POINT('',(0.,28.6423096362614,17.));
#1379=VERTEX_POINT('',#1378);
#1380=CARTESIAN_POINT('',(0.,-28.6423096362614,17.));
#1381=VERTEX_POINT('',#1380);
#1382=EDGE_CURVE('E692',#1379,#1381,#1377,.F.);
#1383=ORIENTED_EDGE('',*,*,#1382,.F.);
#1384=CARTESIAN_POINT('',(0.,0.,17.));
#1385=DIRECTION('',(0.,0.,-1.));
#1386=DIRECTION('',(0.,1.,0.));
#1387=AXIS2_PLACEMENT_3D('',#1384,#1385,#1386);
#1388=CIRCLE('',#1387,28.6423096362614);
#1389=CARTESIAN_POINT('',(28.3686534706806,3.94986095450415,17.));
#1390=VERTEX_POINT('',#1389);
#1391=EDGE_CURVE('E346',#1390,#1379,#1388,.F.);
#1392=ORIENTED_EDGE('',*,*,#1391,.F.);
#1393=CARTESIAN_POINT('',(0.,0.,17.));
#1394=DIRECTION('',(0.,0.,-1.));
#1395=DIRECTION('',(0.990445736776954,0.137903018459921,0.));
#1396=AXIS2_PLACEMENT_3D('',#1393,#1394,#1395);
#1397=CIRCLE('',#1396,28.6423096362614);
#1398=CARTESIAN_POINT('',(28.3686534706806,-3.94986095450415,17.));
#1399=VERTEX_POINT('',#1398);
#1400=EDGE_CURVE('E671',#1399,#1390,#1397,.F.);
#1401=ORIENTED_EDGE('',*,*,#1400,.F.);
#1402=CARTESIAN_POINT('',(0.,0.,17.));
#1403=DIRECTION('',(0.,0.,-1.));
#1404=DIRECTION('',(0.990445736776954,-0.13790301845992,0.));
#1405=AXIS2_PLACEMENT_3D('',#1402,#1403,#1404);
#1406=CIRCLE('',#1405,28.6423096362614);
#1407=EDGE_CURVE('E691',#1381,#1399,#1406,.F.);
#1408=ORIENTED_EDGE('',*,*,#1407,.F.);
#1409=EDGE_LOOP('',(#1383,#1392,#1401,#1408));
#1410=FACE_BOUND('',#1409,.T.);
#1411=ADVANCED_FACE('F425',(#1372,#1410),#1362,.F.);
#1412=CARTESIAN_POINT('',(0.,0.,31.2889978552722));
#1413=DIRECTION('',(0.,0.,-1.));
#1414=DIRECTION('',(0.,1.,0.));
#1415=AXIS2_PLACEMENT_3D('',#1412,#1413,#1414);
#1416=CONICAL_SURFACE('',#1415,39.3866648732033,0.261799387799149);
#1417=CARTESIAN_POINT('',(0.,0.,31.2889978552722));
#1418=DIRECTION('',(0.,0.,-1.));
#1419=DIRECTION('',(0.,1.,0.));
#1420=AXIS2_PLACEMENT_3D('',#1417,#1418,#1419);
#1421=CIRCLE('',#1420,39.3866648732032);
#1422=CARTESIAN_POINT('',(0.,39.3866648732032,31.2889978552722));
#1423=VERTEX_POINT('',#1422);
#1424=EDGE_CURVE('E652',#1423,#1423,#1421,.T.);
#1425=ORIENTED_EDGE('',*,*,#1424,.F.);
#1426=EDGE_LOOP('',(#1425));
#1427=FACE_BOUND('',#1426,.T.);
#1428=ORIENTED_EDGE('',*,*,#1309,.T.);
#1429=EDGE_LOOP('',(#1428));
#1430=FACE_BOUND('',#1429,.T.);
#1431=ADVANCED_FACE('F429',(#1427,#1430),#1416,.T.);
#1432=CARTESIAN_POINT('',(29.,0.,27.5));
#1433=DIRECTION('',(0.,0.,1.));
#1434=DIRECTION('',(0.,-1.,0.));
#1435=AXIS2_PLACEMENT_3D('',#1432,#1433,#1434);
#1436=CYLINDRICAL_SURFACE('',#1435,2.4585);
#1437=CARTESIAN_POINT('',(29.,0.,22.0719999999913));
#1438=DIRECTION('',(0.,0.,1.));
#1439=DIRECTION('',(0.,-1.,0.));
#1440=AXIS2_PLACEMENT_3D('',#1437,#1438,#1439);
#1441=CIRCLE('',#1440,2.4585);
#1442=CARTESIAN_POINT('',(29.,-2.45849999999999,22.0719999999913));
#1443=VERTEX_POINT('',#1442);
#1444=EDGE_CURVE('E23',#1443,#1443,#1441,.F.);
#1445=ORIENTED_EDGE('',*,*,#1444,.F.);
#1446=EDGE_LOOP('',(#1445));
#1447=FACE_BOUND('',#1446,.T.);
#1448=CARTESIAN_POINT('',(29.,0.,20.5415000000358));
#1449=DIRECTION('',(0.,0.,-1.));
#1450=DIRECTION('',(-1.,0.,0.));
#1451=AXIS2_PLACEMENT_3D('',#1448,#1449,#1450);
#1452=CIRCLE('',#1451,2.45849999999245);
#1453=CARTESIAN_POINT('',(26.5415000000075,0.,20.5415000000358));
#1454=VERTEX_POINT('',#1453);
#1455=EDGE_CURVE('E250',#1454,#1454,#1452,.T.);
#1456=ORIENTED_EDGE('',*,*,#1455,.T.);
#1457=EDGE_LOOP('',(#1456));
#1458=FACE_BOUND('',#1457,.T.);
#1459=ADVANCED_FACE('F621',(#1447,#1458),#1436,.F.);
#1460=CARTESIAN_POINT('',(29.,0.,20.0000000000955));
#1461=DIRECTION('',(0.,0.,-1.));
#1462=DIRECTION('',(0.,1.,0.));
#1463=AXIS2_PLACEMENT_3D('',#1460,#1461,#1462);
#1464=CONICAL_SURFACE('',#1463,2.9999999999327,0.785398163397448);
#1465=CARTESIAN_POINT('',(29.,0.,19.9999999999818));
#1466=DIRECTION('',(0.,0.,-1.));
#1467=DIRECTION('',(0.,1.,0.));
#1468=AXIS2_PLACEMENT_3D('',#1465,#1466,#1467);
#1469=CIRCLE('',#1468,3.00000000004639);
#1470=CARTESIAN_POINT('',(29.,3.00000000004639,19.9999999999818));
#1471=VERTEX_POINT('',#1470);
#1472=EDGE_CURVE('E568',#1471,#1471,#1469,.T.);
#1473=ORIENTED_EDGE('',*,*,#1472,.T.);
#1474=EDGE_LOOP('',(#1473));
#1475=FACE_BOUND('',#1474,.T.);
#1476=ORIENTED_EDGE('',*,*,#1455,.F.);
#1477=EDGE_LOOP('',(#1476));
#1478=FACE_BOUND('',#1477,.T.);
#1479=ADVANCED_FACE('F618',(#1475,#1478),#1464,.F.);
#1480=CARTESIAN_POINT('',(25.5,0.,20.));
#1481=DIRECTION('',(0.,0.,1.));
#1482=DIRECTION('',(0.,-1.,0.));
#1483=AXIS2_PLACEMENT_3D('',#1480,#1481,#1482);
#1484=PLANE('',#1483);
#1485=ORIENTED_EDGE('',*,*,#1472,.F.);
#1486=EDGE_LOOP('',(#1485));
#1487=FACE_BOUND('',#1486,.T.);
#1488=CARTESIAN_POINT('',(29.,0.,20.));
#1489=DIRECTION('',(0.,0.,1.));
#1490=DIRECTION('',(0.,-1.,0.));
#1491=AXIS2_PLACEMENT_3D('',#1488,#1489,#1490);
#1492=CIRCLE('',#1491,4.);
#1493=CARTESIAN_POINT('',(29.,-4.,20.));
#1494=VERTEX_POINT('',#1493);
#1495=EDGE_CURVE('E687',#1494,#1494,#1492,.F.);
#1496=ORIENTED_EDGE('',*,*,#1495,.T.);
#1497=EDGE_LOOP('',(#1496));
#1498=FACE_BOUND('',#1497,.T.);
#1499=ADVANCED_FACE('F576',(#1487,#1498),#1484,.F.);
#1500=CARTESIAN_POINT('',(29.,0.,18.5));
#1501=DIRECTION('',(0.,0.,1.));
#1502=DIRECTION('',(0.,-1.,0.));
#1503=AXIS2_PLACEMENT_3D('',#1500,#1501,#1502);
#1504=CYLINDRICAL_SURFACE('',#1503,4.);
#1505=CARTESIAN_POINT('',(29.,0.,17.));
#1506=DIRECTION('',(0.,0.,1.));
#1507=DIRECTION('',(0.,-1.,0.));
#1508=AXIS2_PLACEMENT_3D('',#1505,#1506,#1507);
#1509=CIRCLE('',#1508,4.);
#1510=EDGE_CURVE('E654',#1399,#1390,#1509,.T.);
#1511=ORIENTED_EDGE('',*,*,#1510,.F.);
#1512=CARTESIAN_POINT('',(29.,0.,17.));
#1513=DIRECTION('',(0.,0.,1.));
#1514=DIRECTION('',(0.,-1.,0.));
#1515=AXIS2_PLACEMENT_3D('',#1512,#1513,#1514);
#1516=CIRCLE('',#1515,4.);
#1517=EDGE_CURVE('E684',#1390,#1399,#1516,.T.);
#1518=ORIENTED_EDGE('',*,*,#1517,.F.);
#1519=EDGE_LOOP('',(#1511,#1518));
#1520=FACE_BOUND('',#1519,.T.);
#1521=ORIENTED_EDGE('',*,*,#1495,.F.);
#1522=EDGE_LOOP('',(#1521));
#1523=FACE_BOUND('',#1522,.T.);
#1524=ADVANCED_FACE('F360',(#1520,#1523),#1504,.F.);
#1525=CARTESIAN_POINT('',(-31.3211548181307,0.,17.));
#1526=DIRECTION('',(0.,0.,-1.));
#1527=DIRECTION('',(1.,0.,0.));
#1528=AXIS2_PLACEMENT_3D('',#1525,#1526,#1527);
#1529=PLANE('',#1528);
#1530=CARTESIAN_POINT('',(0.,0.,17.));
#1531=DIRECTION('',(0.,0.,1.));
#1532=DIRECTION('',(0.,-1.,0.));
#1533=AXIS2_PLACEMENT_3D('',#1530,#1531,#1532);
#1534=CIRCLE('',#1533,34.);
#1535=CARTESIAN_POINT('',(0.,-34.,17.));
#1536=VERTEX_POINT('',#1535);
#1537=CARTESIAN_POINT('',(0.,34.,17.));
#1538=VERTEX_POINT('',#1537);
#1539=EDGE_CURVE('E306',#1536,#1538,#1534,.T.);
#1540=ORIENTED_EDGE('',*,*,#1539,.F.);
#1541=CARTESIAN_POINT('',(0.,0.,17.));
#1542=DIRECTION('',(0.,0.,1.));
#1543=DIRECTION('',(-1.,0.,0.));
#1544=AXIS2_PLACEMENT_3D('',#1541,#1542,#1543);
#1545=CIRCLE('',#1544,34.);
#1546=CARTESIAN_POINT('',(-34.,0.,17.));
#1547=VERTEX_POINT('',#1546);
#1548=EDGE_CURVE('E398',#1547,#1536,#1545,.T.);
#1549=ORIENTED_EDGE('',*,*,#1548,.F.);
#1550=CARTESIAN_POINT('',(0.,0.,17.));
#1551=DIRECTION('',(0.,0.,1.));
#1552=DIRECTION('',(0.,1.,0.));
#1553=AXIS2_PLACEMENT_3D('',#1550,#1551,#1552);
#1554=CIRCLE('',#1553,34.);
#1555=EDGE_CURVE('E399',#1538,#1547,#1554,.T.);
#1556=ORIENTED_EDGE('',*,*,#1555,.F.);
#1557=EDGE_LOOP('',(#1540,#1549,#1556));
#1558=FACE_BOUND('',#1557,.T.);
#1559=ORIENTED_EDGE('',*,*,#1382,.T.);
#1560=ORIENTED_EDGE('',*,*,#1407,.T.);
#1561=ORIENTED_EDGE('',*,*,#1510,.T.);
#1562=ORIENTED_EDGE('',*,*,#1391,.T.);
#1563=EDGE_LOOP('',(#1559,#1560,#1561,#1562));
#1564=FACE_BOUND('',#1563,.T.);
#1565=ADVANCED_FACE('F351',(#1558,#1564),#1529,.T.);
#1566=CARTESIAN_POINT('',(27.,0.,17.));
#1567=DIRECTION('',(0.,0.,-1.));
#1568=DIRECTION('',(0.,1.,0.));
#1569=AXIS2_PLACEMENT_3D('',#1566,#1567,#1568);
#1570=PLANE('',#1569);
#1571=ORIENTED_EDGE('',*,*,#1517,.T.);
#1572=ORIENTED_EDGE('',*,*,#1400,.T.);
#1573=EDGE_LOOP('',(#1571,#1572));
#1574=FACE_BOUND('',#1573,.T.);
#1575=ADVANCED_FACE('F325',(#1574),#1570,.F.);
#1576=CARTESIAN_POINT('',(0.,0.,23.));
#1577=DIRECTION('',(0.,0.,-1.));
#1578=DIRECTION('',(0.,1.,0.));
#1579=AXIS2_PLACEMENT_3D('',#1576,#1577,#1578);
#1580=TOROIDAL_SURFACE('',#1579,34.,6.);
#1581=ORIENTED_EDGE('',*,*,#1539,.T.);
#1582=ORIENTED_EDGE('',*,*,#1555,.T.);
#1583=ORIENTED_EDGE('',*,*,#1548,.T.);
#1584=EDGE_LOOP('',(#1581,#1582,#1583));
#1585=FACE_BOUND('',#1584,.T.);
#1586=CARTESIAN_POINT('',(0.,0.,23.));
#1587=DIRECTION('',(0.,0.,-1.));
#1588=DIRECTION('',(0.,1.,0.));
#1589=AXIS2_PLACEMENT_3D('',#1586,#1587,#1588);
#1590=CIRCLE('',#1589,40.);
#1591=CARTESIAN_POINT('',(0.,40.,23.));
#1592=VERTEX_POINT('',#1591);
#1593=EDGE_CURVE('E400',#1592,#1592,#1590,.T.);
#1594=ORIENTED_EDGE('',*,*,#1593,.T.);
#1595=EDGE_LOOP('',(#1594));
#1596=FACE_BOUND('',#1595,.T.);
#1597=ADVANCED_FACE('F313',(#1585,#1596),#1580,.T.);
#1598=CARTESIAN_POINT('',(0.,0.,26.630255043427));
#1599=DIRECTION('',(0.,0.,-1.));
#1600=DIRECTION('',(0.,1.,0.));
#1601=AXIS2_PLACEMENT_3D('',#1598,#1599,#1600);
#1602=TOROIDAL_SURFACE('',#1601,22.0000000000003,17.9999999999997);
#1603=ORIENTED_EDGE('',*,*,#1424,.T.);
#1604=EDGE_LOOP('',(#1603));
#1605=FACE_BOUND('',#1604,.T.);
#1606=CARTESIAN_POINT('',(0.,0.,26.6302550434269));
#1607=DIRECTION('',(0.,0.,1.));
#1608=DIRECTION('',(0.,-1.,0.));
#1609=AXIS2_PLACEMENT_3D('',#1606,#1607,#1608);
#1610=CIRCLE('',#1609,40.);
#1611=CARTESIAN_POINT('',(0.,-40.,26.6302550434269));
#1612=VERTEX_POINT('',#1611);
#1613=EDGE_CURVE('E403',#1612,#1612,#1610,.F.);
#1614=ORIENTED_EDGE('',*,*,#1613,.F.);
#1615=EDGE_LOOP('',(#1614));
#1616=FACE_BOUND('',#1615,.T.);
#1617=ADVANCED_FACE('F324',(#1605,#1616),#1602,.T.);
#1618=CARTESIAN_POINT('',(0.,0.,24.8151275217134));
#1619=DIRECTION('',(0.,0.,1.));
#1620=DIRECTION('',(0.,-1.,0.));
#1621=AXIS2_PLACEMENT_3D('',#1618,#1619,#1620);
#1622=CYLINDRICAL_SURFACE('',#1621,40.);
#1623=ORIENTED_EDGE('',*,*,#1613,.T.);
#1624=EDGE_LOOP('',(#1623));
#1625=FACE_BOUND('',#1624,.T.);
#1626=ORIENTED_EDGE('',*,*,#1593,.F.);
#1627=EDGE_LOOP('',(#1626));
#1628=FACE_BOUND('',#1627,.T.);
#1629=ADVANCED_FACE('F328',(#1625,#1628),#1622,.T.);
#1630=CARTESIAN_POINT('',(29.,1.19325,22.));
#1631=DIRECTION('',(0.,0.,-1.));
#1632=DIRECTION('',(0.,1.,0.));
#1633=AXIS2_PLACEMENT_3D('',#1630,#1631,#1632);
#1634=PLANE('',#1633);
#1635=CARTESIAN_POINT('',(29.,0.,21.9999999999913));
#1636=DIRECTION('',(0.,0.,1.));
#1637=DIRECTION('',(0.,-1.,0.));
#1638=AXIS2_PLACEMENT_3D('',#1635,#1636,#1637);
#1639=CIRCLE('',#1638,2.38650000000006);
#1640=CARTESIAN_POINT('',(29.,-2.38650000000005,21.9999999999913));
#1641=VERTEX_POINT('',#1640);
#1642=EDGE_CURVE('E806',#1641,#1641,#1639,.T.);
#1643=ORIENTED_EDGE('',*,*,#1642,.F.);
#1644=EDGE_LOOP('',(#1643));
#1645=FACE_BOUND('',#1644,.T.);
#1646=DIRECTION('',(0.,1.,0.));
#1647=VECTOR('',#1646,1.);
#1648=CARTESIAN_POINT('',(30.5,0.866025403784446,22.));
#1649=LINE('',#1648,#1647);
#1650=CARTESIAN_POINT('',(30.5,-0.866025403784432,22.));
#1651=VERTEX_POINT('',#1650);
#1652=CARTESIAN_POINT('',(30.5,0.866025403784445,22.));
#1653=VERTEX_POINT('',#1652);
#1654=EDGE_CURVE('E828',#1651,#1653,#1649,.T.);
#1655=ORIENTED_EDGE('',*,*,#1654,.T.);
#1656=DIRECTION('',(-0.86602540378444,0.5,0.));
#1657=VECTOR('',#1656,1.);
#1658=CARTESIAN_POINT('',(30.5,0.866025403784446,22.));
#1659=LINE('',#1658,#1657);
#1660=CARTESIAN_POINT('',(29.,1.73205080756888,22.));
#1661=VERTEX_POINT('',#1660);
#1662=EDGE_CURVE('E803',#1653,#1661,#1659,.T.);
#1663=ORIENTED_EDGE('',*,*,#1662,.T.);
#1664=DIRECTION('',(-0.866025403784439,-0.5,0.));
#1665=VECTOR('',#1664,1.);
#1666=CARTESIAN_POINT('',(27.5,0.866025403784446,22.));
#1667=LINE('',#1666,#1665);
#1668=CARTESIAN_POINT('',(27.5,0.866025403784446,22.));
#1669=VERTEX_POINT('',#1668);
#1670=EDGE_CURVE('E825',#1661,#1669,#1667,.T.);
#1671=ORIENTED_EDGE('',*,*,#1670,.T.);
#1672=DIRECTION('',(0.,-1.,0.));
#1673=VECTOR('',#1672,1.);
#1674=CARTESIAN_POINT('',(27.5,-0.866025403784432,22.));
#1675=LINE('',#1674,#1673);
#1676=CARTESIAN_POINT('',(27.5,-0.866025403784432,22.));
#1677=VERTEX_POINT('',#1676);
#1678=EDGE_CURVE('E840',#1669,#1677,#1675,.T.);
#1679=ORIENTED_EDGE('',*,*,#1678,.T.);
#1680=DIRECTION('',(0.866025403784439,-0.5,0.));
#1681=VECTOR('',#1680,1.);
#1682=CARTESIAN_POINT('',(29.,-1.73205080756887,22.));
#1683=LINE('',#1682,#1681);
#1684=CARTESIAN_POINT('',(29.,-1.73205080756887,22.));
#1685=VERTEX_POINT('',#1684);
#1686=EDGE_CURVE('E420',#1677,#1685,#1683,.T.);
#1687=ORIENTED_EDGE('',*,*,#1686,.T.);
#1688=DIRECTION('',(0.866025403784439,0.5,0.));
#1689=VECTOR('',#1688,1.);
#1690=CARTESIAN_POINT('',(30.5,-0.866025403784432,22.));
#1691=LINE('',#1690,#1689);
#1692=EDGE_CURVE('E846',#1685,#1651,#1691,.T.);
#1693=ORIENTED_EDGE('',*,*,#1692,.T.);
#1694=EDGE_LOOP('',(#1655,#1663,#1671,#1679,#1687,#1693));
#1695=FACE_BOUND('',#1694,.T.);
#1696=ADVANCED_FACE('F633',(#1645,#1695),#1634,.T.);
#1697=CARTESIAN_POINT('',(29.,1.73205080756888,22.));
#1698=DIRECTION('',(0.5,0.866025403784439,0.));
#1699=DIRECTION('',(-0.866025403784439,0.5,0.));
#1700=AXIS2_PLACEMENT_3D('',#1697,#1698,#1699);
#1701=PLANE('',#1700);
#1702=DIRECTION('',(0.,0.,1.));
#1703=VECTOR('',#1702,1.);
#1704=CARTESIAN_POINT('',(29.,1.73205080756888,22.));
#1705=LINE('',#1704,#1703);
#1706=CARTESIAN_POINT('',(29.,1.73205080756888,25.));
#1707=VERTEX_POINT('',#1706);
#1708=EDGE_CURVE('E810',#1661,#1707,#1705,.T.);
#1709=ORIENTED_EDGE('',*,*,#1708,.F.);
#1710=ORIENTED_EDGE('',*,*,#1662,.F.);
#1711=DIRECTION('',(0.,0.,1.));
#1712=VECTOR('',#1711,1.);
#1713=CARTESIAN_POINT('',(30.5,0.866025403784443,22.));
#1714=LINE('',#1713,#1712);
#1715=CARTESIAN_POINT('',(30.5,0.866025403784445,25.));
#1716=VERTEX_POINT('',#1715);
#1717=EDGE_CURVE('E813',#1716,#1653,#1714,.F.);
#1718=ORIENTED_EDGE('',*,*,#1717,.F.);
#1719=DIRECTION('',(-0.866025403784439,0.5,0.));
#1720=VECTOR('',#1719,1.);
#1721=CARTESIAN_POINT('',(29.,1.73205080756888,25.));
#1722=LINE('',#1721,#1720);
#1723=EDGE_CURVE('E807',#1707,#1716,#1722,.F.);
#1724=ORIENTED_EDGE('',*,*,#1723,.F.);
#1725=EDGE_LOOP('',(#1709,#1710,#1718,#1724));
#1726=FACE_BOUND('',#1725,.T.);
#1727=ADVANCED_FACE('F639',(#1726),#1701,.F.);
#1728=CARTESIAN_POINT('',(29.,0.,25.));
#1729=DIRECTION('',(0.,0.,1.));
#1730=DIRECTION('',(0.,-1.,0.));
#1731=AXIS2_PLACEMENT_3D('',#1728,#1729,#1730);
#1732=PLANE('',#1731);
#1733=ORIENTED_EDGE('',*,*,#1723,.T.);
#1734=DIRECTION('',(0.,-1.,0.));
#1735=VECTOR('',#1734,1.);
#1736=CARTESIAN_POINT('',(30.5,0.,25.));
#1737=LINE('',#1736,#1735);
#1738=CARTESIAN_POINT('',(30.5,-0.866025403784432,25.));
#1739=VERTEX_POINT('',#1738);
#1740=EDGE_CURVE('E819',#1739,#1716,#1737,.F.);
#1741=ORIENTED_EDGE('',*,*,#1740,.F.);
#1742=DIRECTION('',(0.866025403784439,0.5,0.));
#1743=VECTOR('',#1742,1.);
#1744=CARTESIAN_POINT('',(30.5,-0.866025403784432,25.));
#1745=LINE('',#1744,#1743);
#1746=CARTESIAN_POINT('',(29.,-1.73205080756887,25.));
#1747=VERTEX_POINT('',#1746);
#1748=EDGE_CURVE('E843',#1739,#1747,#1745,.F.);
#1749=ORIENTED_EDGE('',*,*,#1748,.T.);
#1750=DIRECTION('',(0.866025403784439,-0.5,0.));
#1751=VECTOR('',#1750,1.);
#1752=CARTESIAN_POINT('',(29.,-1.73205080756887,25.));
#1753=LINE('',#1752,#1751);
#1754=CARTESIAN_POINT('',(27.5,-0.866025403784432,25.));
#1755=VERTEX_POINT('',#1754);
#1756=EDGE_CURVE('E852',#1747,#1755,#1753,.F.);
#1757=ORIENTED_EDGE('',*,*,#1756,.T.);
#1758=DIRECTION('',(0.,-1.,0.));
#1759=VECTOR('',#1758,1.);
#1760=CARTESIAN_POINT('',(27.5,-0.866025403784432,25.));
#1761=LINE('',#1760,#1759);
#1762=CARTESIAN_POINT('',(27.5,0.866025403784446,25.));
#1763=VERTEX_POINT('',#1762);
#1764=EDGE_CURVE('E834',#1755,#1763,#1761,.F.);
#1765=ORIENTED_EDGE('',*,*,#1764,.T.);
#1766=DIRECTION('',(-0.86602540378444,-0.5,0.));
#1767=VECTOR('',#1766,1.);
#1768=CARTESIAN_POINT('',(29.,1.73205080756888,25.));
#1769=LINE('',#1768,#1767);
#1770=EDGE_CURVE('E816',#1707,#1763,#1769,.T.);
#1771=ORIENTED_EDGE('',*,*,#1770,.F.);
#1772=EDGE_LOOP('',(#1733,#1741,#1749,#1757,#1765,#1771));
#1773=FACE_BOUND('',#1772,.T.);
#1774=ADVANCED_FACE('F897',(#1773),#1732,.F.);
#1775=CARTESIAN_POINT('',(27.5,0.866025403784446,22.));
#1776=DIRECTION('',(-0.5,0.866025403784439,0.));
#1777=DIRECTION('',(-0.866025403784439,-0.5,0.));
#1778=AXIS2_PLACEMENT_3D('',#1775,#1776,#1777);
#1779=PLANE('',#1778);
#1780=DIRECTION('',(0.,0.,1.));
#1781=VECTOR('',#1780,1.);
#1782=CARTESIAN_POINT('',(27.5,0.866025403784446,22.));
#1783=LINE('',#1782,#1781);
#1784=EDGE_CURVE('E822',#1669,#1763,#1783,.T.);
#1785=ORIENTED_EDGE('',*,*,#1784,.F.);
#1786=ORIENTED_EDGE('',*,*,#1670,.F.);
#1787=ORIENTED_EDGE('',*,*,#1708,.T.);
#1788=ORIENTED_EDGE('',*,*,#1770,.T.);
#1789=EDGE_LOOP('',(#1785,#1786,#1787,#1788));
#1790=FACE_BOUND('',#1789,.T.);
#1791=ADVANCED_FACE('F893',(#1790),#1779,.F.);
#1792=CARTESIAN_POINT('',(30.5,0.866025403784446,22.));
#1793=DIRECTION('',(1.,0.,0.));
#1794=DIRECTION('',(0.,1.,0.));
#1795=AXIS2_PLACEMENT_3D('',#1792,#1793,#1794);
#1796=PLANE('',#1795);
#1797=ORIENTED_EDGE('',*,*,#1717,.T.);
#1798=ORIENTED_EDGE('',*,*,#1654,.F.);
#1799=DIRECTION('',(0.,0.,1.));
#1800=VECTOR('',#1799,1.);
#1801=CARTESIAN_POINT('',(30.5,-0.866025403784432,22.));
#1802=LINE('',#1801,#1800);
#1803=EDGE_CURVE('E831',#1739,#1651,#1802,.F.);
#1804=ORIENTED_EDGE('',*,*,#1803,.F.);
#1805=ORIENTED_EDGE('',*,*,#1740,.T.);
#1806=EDGE_LOOP('',(#1797,#1798,#1804,#1805));
#1807=FACE_BOUND('',#1806,.T.);
#1808=ADVANCED_FACE('F881',(#1807),#1796,.F.);
#1809=CARTESIAN_POINT('',(27.5,-0.866025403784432,22.));
#1810=DIRECTION('',(-1.,0.,0.));
#1811=DIRECTION('',(0.,-1.,0.));
#1812=AXIS2_PLACEMENT_3D('',#1809,#1810,#1811);
#1813=PLANE('',#1812);
#1814=DIRECTION('',(0.,0.,1.));
#1815=VECTOR('',#1814,1.);
#1816=CARTESIAN_POINT('',(27.5,-0.866025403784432,22.));
#1817=LINE('',#1816,#1815);
#1818=EDGE_CURVE('E837',#1677,#1755,#1817,.T.);
#1819=ORIENTED_EDGE('',*,*,#1818,.F.);
#1820=ORIENTED_EDGE('',*,*,#1678,.F.);
#1821=ORIENTED_EDGE('',*,*,#1784,.T.);
#1822=ORIENTED_EDGE('',*,*,#1764,.F.);
#1823=EDGE_LOOP('',(#1819,#1820,#1821,#1822));
#1824=FACE_BOUND('',#1823,.T.);
#1825=ADVANCED_FACE('F907',(#1824),#1813,.F.);
#1826=CARTESIAN_POINT('',(30.5,-0.866025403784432,22.));
#1827=DIRECTION('',(0.5,-0.866025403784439,0.));
#1828=DIRECTION('',(0.866025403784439,0.5,0.));
#1829=AXIS2_PLACEMENT_3D('',#1826,#1827,#1828);
#1830=PLANE('',#1829);
#1831=ORIENTED_EDGE('',*,*,#1803,.T.);
#1832=ORIENTED_EDGE('',*,*,#1692,.F.);
#1833=DIRECTION('',(0.,0.,1.));
#1834=VECTOR('',#1833,1.);
#1835=CARTESIAN_POINT('',(29.,-1.73205080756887,22.));
#1836=LINE('',#1835,#1834);
#1837=EDGE_CURVE('E849',#1747,#1685,#1836,.F.);
#1838=ORIENTED_EDGE('',*,*,#1837,.F.);
#1839=ORIENTED_EDGE('',*,*,#1748,.F.);
#1840=EDGE_LOOP('',(#1831,#1832,#1838,#1839));
#1841=FACE_BOUND('',#1840,.T.);
#1842=ADVANCED_FACE('F1024',(#1841),#1830,.F.);
#1843=CARTESIAN_POINT('',(29.,-1.73205080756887,22.));
#1844=DIRECTION('',(-0.5,-0.866025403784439,0.));
#1845=DIRECTION('',(0.866025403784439,-0.5,0.));
#1846=AXIS2_PLACEMENT_3D('',#1843,#1844,#1845);
#1847=PLANE('',#1846);
#1848=ORIENTED_EDGE('',*,*,#1837,.T.);
#1849=ORIENTED_EDGE('',*,*,#1686,.F.);
#1850=ORIENTED_EDGE('',*,*,#1818,.T.);
#1851=ORIENTED_EDGE('',*,*,#1756,.F.);
#1852=EDGE_LOOP('',(#1848,#1849,#1850,#1851));
#1853=FACE_BOUND('',#1852,.T.);
#1854=ADVANCED_FACE('F326',(#1853),#1847,.F.);
#1855=CARTESIAN_POINT('',(29.,0.,22.6135000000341));
#1856=DIRECTION('',(0.,0.,1.));
#1857=DIRECTION('',(0.,-1.,0.));
#1858=AXIS2_PLACEMENT_3D('',#1855,#1856,#1857);
#1859=CONICAL_SURFACE('',#1858,3.00000000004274,0.785398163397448);
#1860=ORIENTED_EDGE('',*,*,#1642,.T.);
#1861=EDGE_LOOP('',(#1860));
#1862=FACE_BOUND('',#1861,.T.);
#1863=ORIENTED_EDGE('',*,*,#1444,.T.);
#1864=EDGE_LOOP('',(#1863));
#1865=FACE_BOUND('',#1864,.T.);
#1866=ADVANCED_FACE('F642',(#1862,#1865),#1859,.T.);
#1867=CARTESIAN_POINT('',(29.,3.63075,35.));
#1868=DIRECTION('',(0.,0.,-1.));
#1869=DIRECTION('',(0.,1.,0.));
#1870=AXIS2_PLACEMENT_3D('',#1867,#1868,#1869);
#1871=PLANE('',#1870);
#1872=ORIENTED_EDGE('',*,*,#133,.F.);
#1873=ORIENTED_EDGE('',*,*,#126,.F.);
#1874=ORIENTED_EDGE('',*,*,#117,.F.);
#1875=EDGE_LOOP('',(#1872,#1873,#1874));
#1876=FACE_BOUND('',#1875,.T.);
#1877=CARTESIAN_POINT('',(29.,0.,35.));
#1878=DIRECTION('',(0.,0.,1.));
#1879=DIRECTION('',(0.,-1.,0.));
#1880=AXIS2_PLACEMENT_3D('',#1877,#1878,#1879);
#1881=CIRCLE('',#1880,4.875);
#1882=CARTESIAN_POINT('',(29.,-4.87499999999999,35.));
#1883=VERTEX_POINT('',#1882);
#1884=EDGE_CURVE('E863',#1883,#1883,#1881,.T.);
#1885=ORIENTED_EDGE('',*,*,#1884,.F.);
#1886=EDGE_LOOP('',(#1885));
#1887=FACE_BOUND('',#1886,.T.);
#1888=ADVANCED_FACE('F761',(#1876,#1887),#1871,.T.);
#1889=CARTESIAN_POINT('',(29.,0.,35.15));
#1890=DIRECTION('',(0.,0.,1.));
#1891=DIRECTION('',(0.,-1.,0.));
#1892=AXIS2_PLACEMENT_3D('',#1889,#1890,#1891);
#1893=CYLINDRICAL_SURFACE('',#1892,4.875);
#1894=ORIENTED_EDGE('',*,*,#1884,.T.);
#1895=EDGE_LOOP('',(#1894));
#1896=FACE_BOUND('',#1895,.T.);
#1897=CARTESIAN_POINT('',(29.,0.,35.3));
#1898=DIRECTION('',(0.,0.,1.));
#1899=DIRECTION('',(0.,-1.,0.));
#1900=AXIS2_PLACEMENT_3D('',#1897,#1898,#1899);
#1901=CIRCLE('',#1900,4.875);
#1902=CARTESIAN_POINT('',(29.,-4.87499999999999,35.3));
#1903=VERTEX_POINT('',#1902);
#1904=EDGE_CURVE('E860',#1903,#1903,#1901,.T.);
#1905=ORIENTED_EDGE('',*,*,#1904,.F.);
#1906=EDGE_LOOP('',(#1905));
#1907=FACE_BOUND('',#1906,.T.);
#1908=ADVANCED_FACE('F758',(#1896,#1907),#1893,.T.);
#1909=CARTESIAN_POINT('',(29.,5.6875,35.3));
#1910=DIRECTION('',(0.,0.,-1.));
#1911=DIRECTION('',(0.,1.,0.));
#1912=AXIS2_PLACEMENT_3D('',#1909,#1910,#1911);
#1913=PLANE('',#1912);
#1914=CARTESIAN_POINT('',(29.,0.,35.3));
#1915=DIRECTION('',(0.,0.,1.));
#1916=DIRECTION('',(0.,-1.,0.));
#1917=AXIS2_PLACEMENT_3D('',#1914,#1915,#1916);
#1918=CIRCLE('',#1917,6.5);
#1919=CARTESIAN_POINT('',(29.,-6.49999999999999,35.3));
#1920=VERTEX_POINT('',#1919);
#1921=EDGE_CURVE('E857',#1920,#1920,#1918,.T.);
#1922=ORIENTED_EDGE('',*,*,#1921,.F.);
#1923=EDGE_LOOP('',(#1922));
#1924=FACE_BOUND('',#1923,.T.);
#1925=ORIENTED_EDGE('',*,*,#1904,.T.);
#1926=EDGE_LOOP('',(#1925));
#1927=FACE_BOUND('',#1926,.T.);
#1928=ADVANCED_FACE('F754',(#1924,#1927),#1913,.T.);
#1929=CARTESIAN_POINT('',(29.,0.,42.65));
#1930=DIRECTION('',(0.,0.,1.));
#1931=DIRECTION('',(0.,-1.,0.));
#1932=AXIS2_PLACEMENT_3D('',#1929,#1930,#1931);
#1933=CYLINDRICAL_SURFACE('',#1932,6.5);
#1934=ORIENTED_EDGE('',*,*,#1921,.T.);
#1935=EDGE_LOOP('',(#1934));
#1936=FACE_BOUND('',#1935,.T.);
#1937=CARTESIAN_POINT('',(29.,0.,50.));
#1938=DIRECTION('',(0.,0.,-1.));
#1939=DIRECTION('',(-1.,0.,0.));
#1940=AXIS2_PLACEMENT_3D('',#1937,#1938,#1939);
#1941=CIRCLE('',#1940,6.5);
#1942=CARTESIAN_POINT('',(22.5,0.,50.));
#1943=VERTEX_POINT('',#1942);
#1944=EDGE_CURVE('E799',#1943,#1943,#1941,.F.);
#1945=ORIENTED_EDGE('',*,*,#1944,.F.);
#1946=EDGE_LOOP('',(#1945));
#1947=FACE_BOUND('',#1946,.T.);
#1948=ADVANCED_FACE('F745',(#1936,#1947),#1933,.T.);
#1949=CARTESIAN_POINT('',(29.,0.,51.25));
#1950=DIRECTION('',(0.,0.,-1.));
#1951=DIRECTION('',(-1.,0.,0.));
#1952=AXIS2_PLACEMENT_3D('',#1949,#1950,#1951);
#1953=TOROIDAL_SURFACE('',#1952,6.5,1.25);
#1954=CARTESIAN_POINT('',(29.,0.,51.25));
#1955=DIRECTION('',(0.,0.,1.));
#1956=DIRECTION('',(0.,-1.,0.));
#1957=AXIS2_PLACEMENT_3D('',#1954,#1955,#1956);
#1958=CIRCLE('',#1957,7.75);
#1959=CARTESIAN_POINT('',(29.,-7.74999999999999,51.25));
#1960=VERTEX_POINT('',#1959);
#1961=EDGE_CURVE('E792',#1960,#1960,#1958,.T.);
#1962=ORIENTED_EDGE('',*,*,#1961,.F.);
#1963=EDGE_LOOP('',(#1962));
#1964=FACE_BOUND('',#1963,.T.);
#1965=ORIENTED_EDGE('',*,*,#1944,.T.);
#1966=EDGE_LOOP('',(#1965));
#1967=FACE_BOUND('',#1966,.T.);
#1968=ADVANCED_FACE('F740',(#1964,#1967),#1953,.T.);
#1969=CARTESIAN_POINT('',(29.,0.,61.75));
#1970=DIRECTION('',(0.,0.,1.));
#1971=DIRECTION('',(0.,-1.,0.));
#1972=AXIS2_PLACEMENT_3D('',#1969,#1970,#1971);
#1973=CYLINDRICAL_SURFACE('',#1972,7.75);
#1974=CARTESIAN_POINT('',(29.,0.,72.25));
#1975=DIRECTION('',(0.,0.,1.));
#1976=DIRECTION('',(0.,-1.,0.));
#1977=AXIS2_PLACEMENT_3D('',#1974,#1975,#1976);
#1978=CIRCLE('',#1977,7.75);
#1979=CARTESIAN_POINT('',(29.,-7.74999999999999,72.25));
#1980=VERTEX_POINT('',#1979);
#1981=EDGE_CURVE('E794',#1980,#1980,#1978,.F.);
#1982=ORIENTED_EDGE('',*,*,#1981,.T.);
#1983=EDGE_LOOP('',(#1982));
#1984=FACE_BOUND('',#1983,.T.);
#1985=ORIENTED_EDGE('',*,*,#1961,.T.);
#1986=EDGE_LOOP('',(#1985));
#1987=FACE_BOUND('',#1986,.T.);
#1988=ADVANCED_FACE('F744',(#1984,#1987),#1973,.T.);
#1989=CARTESIAN_POINT('',(29.,0.,72.25));
#1990=DIRECTION('',(0.,0.,1.));
#1991=DIRECTION('',(0.,1.,0.));
#1992=AXIS2_PLACEMENT_3D('',#1989,#1990,#1991);
#1993=SPHERICAL_SURFACE('',#1992,7.75);
#1994=CARTESIAN_POINT('',(29.,0.,80.));
#1995=VERTEX_POINT('',#1994);
#1996=VERTEX_LOOP('',#1995);
#1997=FACE_BOUND('',#1996,.T.);
#1998=ORIENTED_EDGE('',*,*,#1981,.F.);
#1999=EDGE_LOOP('',(#1998));
#2000=FACE_BOUND('',#1999,.T.);
#2001=ADVANCED_FACE('F748',(#1997,#2000),#1993,.T.);
#2002=CARTESIAN_POINT('',(0.,0.,0.7));
#2003=DIRECTION('',(0.,0.,-1.));
#2004=DIRECTION('',(1.,0.,0.));
#2005=AXIS2_PLACEMENT_3D('',#2002,#2003,#2004);
#2006=TOROIDAL_SURFACE('',#2005,12.,0.5);
#2007=CARTESIAN_POINT('',(0.,0.,0.7));
#2008=DIRECTION('',(0.,0.,-1.));
#2009=DIRECTION('',(1.,0.,0.));
#2010=AXIS2_PLACEMENT_3D('',#2007,#2008,#2009);
#2011=CIRCLE('',#2010,12.5);
#2012=CARTESIAN_POINT('',(12.5,0.,0.7));
#2013=VERTEX_POINT('',#2012);
#2014=EDGE_CURVE('E301',#2013,#2013,#2011,.T.);
#2015=ORIENTED_EDGE('',*,*,#2014,.T.);
#2016=EDGE_LOOP('',(#2015));
#2017=FACE_BOUND('',#2016,.T.);
#2018=CARTESIAN_POINT('',(0.,0.,0.2));
#2019=DIRECTION('',(0.,0.,-1.));
#2020=DIRECTION('',(1.,0.,0.));
#2021=AXIS2_PLACEMENT_3D('',#2018,#2019,#2020);
#2022=CIRCLE('',#2021,12.);
#2023=CARTESIAN_POINT('',(12.,0.,0.2));
#2024=VERTEX_POINT('',#2023);
#2025=EDGE_CURVE('E730',#2024,#2024,#2022,.T.);
#2026=ORIENTED_EDGE('',*,*,#2025,.F.);
#2027=EDGE_LOOP('',(#2026));
#2028=FACE_BOUND('',#2027,.T.);
#2029=ADVANCED_FACE('F725',(#2017,#2028),#2006,.T.);
#2030=CARTESIAN_POINT('',(0.,0.,-4.70383149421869));
#2031=DIRECTION('',(0.,0.,-1.));
#2032=DIRECTION('',(1.,0.,0.));
#2033=AXIS2_PLACEMENT_3D('',#2030,#2031,#2032);
#2034=CYLINDRICAL_SURFACE('',#2033,12.5);
#2035=ORIENTED_EDGE('',*,*,#1331,.T.);
#2036=EDGE_LOOP('',(#2035));
#2037=FACE_BOUND('',#2036,.T.);
#2038=ORIENTED_EDGE('',*,*,#2014,.F.);
#2039=EDGE_LOOP('',(#2038));
#2040=FACE_BOUND('',#2039,.T.);
#2041=ADVANCED_FACE('F722',(#2037,#2040),#2034,.T.);
#2042=CARTESIAN_POINT('',(-2.53125,0.,17.));
#2043=DIRECTION('',(0.,0.,-1.));
#2044=DIRECTION('',(0.,1.,0.));
#2045=AXIS2_PLACEMENT_3D('',#2042,#2043,#2044);
#2046=PLANE('',#2045);
#2047=CARTESIAN_POINT('',(0.,0.,16.9999999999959));
#2048=DIRECTION('',(0.,0.,1.));
#2049=DIRECTION('',(0.,-1.,0.));
#2050=AXIS2_PLACEMENT_3D('',#2047,#2048,#2049);
#2051=CIRCLE('',#2050,5.06249999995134);
#2052=CARTESIAN_POINT('',(0.,-5.06249999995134,16.9999999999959));
#2053=VERTEX_POINT('',#2052);
#2054=EDGE_CURVE('E297',#2053,#2053,#2051,.F.);
#2055=ORIENTED_EDGE('',*,*,#2054,.T.);
#2056=EDGE_LOOP('',(#2055));
#2057=FACE_BOUND('',#2056,.T.);
#2058=ADVANCED_FACE('F16',(#2057),#2046,.T.);
#2059=CARTESIAN_POINT('',(0.,0.,16.999999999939));
#2060=DIRECTION('',(0.,0.,1.));
#2061=DIRECTION('',(0.,-1.,0.));
#2062=AXIS2_PLACEMENT_3D('',#2059,#2060,#2061);
#2063=CONICAL_SURFACE('',#2062,5.0624999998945,0.785398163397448);
#2064=ORIENTED_EDGE('',*,*,#2054,.F.);
#2065=EDGE_LOOP('',(#2064));
#2066=FACE_BOUND('',#2065,.T.);
#2067=CARTESIAN_POINT('',(0.,0.,15.9375));
#2068=DIRECTION('',(0.,0.,1.));
#2069=DIRECTION('',(0.,-1.,0.));
#2070=AXIS2_PLACEMENT_3D('',#2067,#2068,#2069);
#2071=CIRCLE('',#2070,4.);
#2072=CARTESIAN_POINT('',(0.,-4.,15.9375));
#2073=VERTEX_POINT('',#2072);
#2074=EDGE_CURVE('E300',#2073,#2073,#2071,.F.);
#2075=ORIENTED_EDGE('',*,*,#2074,.T.);
#2076=EDGE_LOOP('',(#2075));
#2077=FACE_BOUND('',#2076,.T.);
#2078=ADVANCED_FACE('F952',(#2066,#2077),#2063,.F.);
#2079=CARTESIAN_POINT('',(0.,0.,8.06875));
#2080=DIRECTION('',(0.,0.,1.));
#2081=DIRECTION('',(0.,-1.,0.));
#2082=AXIS2_PLACEMENT_3D('',#2079,#2080,#2081);
#2083=CYLINDRICAL_SURFACE('',#2082,4.);
#2084=ORIENTED_EDGE('',*,*,#2074,.F.);
#2085=EDGE_LOOP('',(#2084));
#2086=FACE_BOUND('',#2085,.T.);
#2087=CARTESIAN_POINT('',(0.,0.,0.199999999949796));
#2088=DIRECTION('',(0.,0.,-1.));
#2089=DIRECTION('',(-1.,0.,0.));
#2090=AXIS2_PLACEMENT_3D('',#2087,#2088,#2089);
#2091=CIRCLE('',#2090,3.99999999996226);
#2092=CARTESIAN_POINT('',(-3.99999999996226,0.,0.199999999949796));
#2093=VERTEX_POINT('',#2092);
#2094=EDGE_CURVE('E296',#2093,#2093,#2091,.T.);
#2095=ORIENTED_EDGE('',*,*,#2094,.T.);
#2096=EDGE_LOOP('',(#2095));
#2097=FACE_BOUND('',#2096,.T.);
#2098=ADVANCED_FACE('F960',(#2086,#2097),#2083,.F.);
#2099=CARTESIAN_POINT('',(0.,0.,0.));
#2100=DIRECTION('',(0.,0.,-1.));
#2101=DIRECTION('',(0.,1.,0.));
#2102=AXIS2_PLACEMENT_3D('',#2099,#2100,#2101);
#2103=CONICAL_SURFACE('',#2102,4.19999999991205,0.785398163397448);
#2104=ORIENTED_EDGE('',*,*,#2094,.F.);
#2105=EDGE_LOOP('',(#2104));
#2106=FACE_BOUND('',#2105,.T.);
#2107=CARTESIAN_POINT('',(0.,0.,0.));
#2108=DIRECTION('',(0.,0.,-1.));
#2109=DIRECTION('',(0.,1.,0.));
#2110=AXIS2_PLACEMENT_3D('',#2107,#2108,#2109);
#2111=CIRCLE('',#2110,4.19999999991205);
#2112=CARTESIAN_POINT('',(0.,4.19999999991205,0.));
#2113=VERTEX_POINT('',#2112);
#2114=EDGE_CURVE('E293',#2113,#2113,#2111,.F.);
#2115=ORIENTED_EDGE('',*,*,#2114,.F.);
#2116=EDGE_LOOP('',(#2115));
#2117=FACE_BOUND('',#2116,.T.);
#2118=ADVANCED_FACE('F968',(#2106,#2117),#2103,.F.);
#2119=CARTESIAN_POINT('',(-6.6,0.,0.));
#2120=DIRECTION('',(0.,0.,-1.));
#2121=DIRECTION('',(1.,0.,0.));
#2122=AXIS2_PLACEMENT_3D('',#2119,#2120,#2121);
#2123=PLANE('',#2122);
#2124=CARTESIAN_POINT('',(0.,0.,0.));
#2125=DIRECTION('',(0.,0.,1.));
#2126=DIRECTION('',(0.,-1.,0.));
#2127=AXIS2_PLACEMENT_3D('',#2124,#2125,#2126);
#2128=CIRCLE('',#2127,9.);
#2129=CARTESIAN_POINT('',(0.,-9.,0.));
#2130=VERTEX_POINT('',#2129);
#2131=EDGE_CURVE('E164',#2130,#2130,#2128,.T.);
#2132=ORIENTED_EDGE('',*,*,#2131,.F.);
#2133=EDGE_LOOP('',(#2132));
#2134=FACE_BOUND('',#2133,.T.);
#2135=ORIENTED_EDGE('',*,*,#2114,.T.);
#2136=EDGE_LOOP('',(#2135));
#2137=FACE_BOUND('',#2136,.T.);
#2138=ADVANCED_FACE('F977',(#2134,#2137),#2123,.T.);
#2139=CARTESIAN_POINT('',(0.,0.,0.1));
#2140=DIRECTION('',(0.,0.,1.));
#2141=DIRECTION('',(0.,-1.,0.));
#2142=AXIS2_PLACEMENT_3D('',#2139,#2140,#2141);
#2143=CYLINDRICAL_SURFACE('',#2142,9.);
#2144=ORIENTED_EDGE('',*,*,#2131,.T.);
#2145=EDGE_LOOP('',(#2144));
#2146=FACE_BOUND('',#2145,.T.);
#2147=CARTESIAN_POINT('',(0.,0.,0.2));
#2148=DIRECTION('',(0.,0.,1.));
#2149=DIRECTION('',(0.,-1.,0.));
#2150=AXIS2_PLACEMENT_3D('',#2147,#2148,#2149);
#2151=CIRCLE('',#2150,9.);
#2152=CARTESIAN_POINT('',(0.,-9.,0.2));
#2153=VERTEX_POINT('',#2152);
#2154=EDGE_CURVE('E175',#2153,#2153,#2151,.T.);
#2155=ORIENTED_EDGE('',*,*,#2154,.F.);
#2156=EDGE_LOOP('',(#2155));
#2157=FACE_BOUND('',#2156,.T.);
#2158=ADVANCED_FACE('F986',(#2146,#2157),#2143,.T.);
#2159=CARTESIAN_POINT('',(-10.,0.,0.2));
#2160=DIRECTION('',(0.,0.,-1.));
#2161=DIRECTION('',(0.,1.,0.));
#2162=AXIS2_PLACEMENT_3D('',#2159,#2160,#2161);
#2163=PLANE('',#2162);
#2164=ORIENTED_EDGE('',*,*,#2154,.T.);
#2165=EDGE_LOOP('',(#2164));
#2166=FACE_BOUND('',#2165,.T.);
#2167=ORIENTED_EDGE('',*,*,#2025,.T.);
#2168=EDGE_LOOP('',(#2167));
#2169=FACE_BOUND('',#2168,.T.);
#2170=ADVANCED_FACE('F271',(#2166,#2169),#2163,.T.);
#2171=CLOSED_SHELL('',(#137,#202,#376,#394,#414,#432,#733,#771,#844,#869,#935,#1029,#1038,#1111,
#1212,#1278,#1296,#1318,#1357,#1411,#1431,#1459,#1479,#1499,#1524,#1565,#1575,#1597,#1617,#1629,
#1696,#1727,#1774,#1791,#1808,#1825,#1842,#1854,#1866,#1888,#1908,#1928,#1948,#1968,#1988,#2001,
#2029,#2041,#2058,#2078,#2098,#2118,#2138,#2158,#2170));
#2172=MANIFOLD_SOLID_BREP('B1',#2171);
#2173=ADVANCED_BREP_SHAPE_REPRESENTATION('',(#18,#2172),#14);
#2174=SHAPE_DEFINITION_REPRESENTATION(#9,#2173);
ENDSEC;
END-ISO-10303-21;
